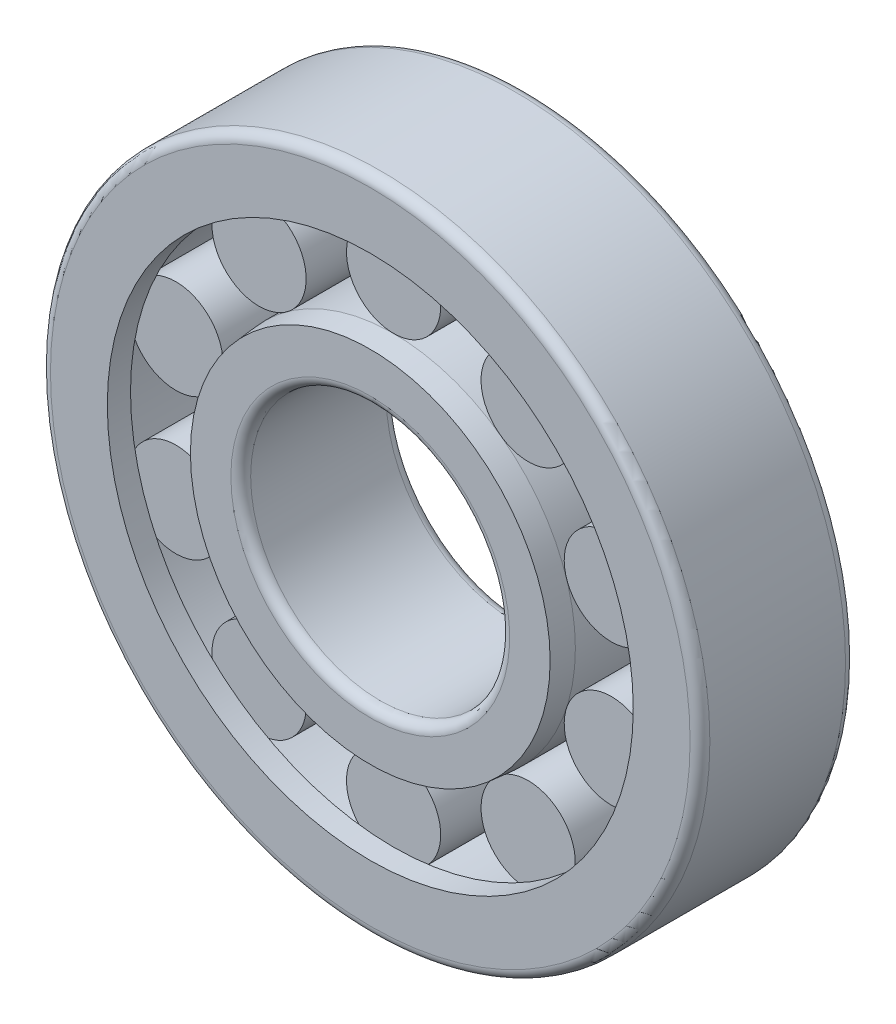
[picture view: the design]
ISO-10303-21;
HEADER;
FILE_DESCRIPTION(('STEP AP214'),'2;1');
FILE_NAME('part.step','',(''),(''),'','','');
FILE_SCHEMA(('AUTOMOTIVE_DESIGN { 1 0 10303 214 1 1 1 1 }'));
ENDSEC;
DATA;
#1=APPLICATION_CONTEXT('core data for automotive mechanical design processes');
#2=APPLICATION_PROTOCOL_DEFINITION('international standard','automotive_design',2000,#1);
#3=PRODUCT_CONTEXT('',#1,'mechanical');
#4=PRODUCT('Part','Part','',(#3));
#5=PRODUCT_RELATED_PRODUCT_CATEGORY('part','',(#4));
#6=PRODUCT_DEFINITION_FORMATION('','',#4);
#7=PRODUCT_DEFINITION_CONTEXT('part definition',#1,'design');
#8=PRODUCT_DEFINITION('design','',#6,#7);
#9=PRODUCT_DEFINITION_SHAPE('','',#8);
#10=(LENGTH_UNIT() NAMED_UNIT(*) SI_UNIT(.MILLI.,.METRE.));
#11=(NAMED_UNIT(*) PLANE_ANGLE_UNIT() SI_UNIT($,.RADIAN.));
#12=(NAMED_UNIT(*) SI_UNIT($,.STERADIAN.) SOLID_ANGLE_UNIT());
#13=UNCERTAINTY_MEASURE_WITH_UNIT(LENGTH_MEASURE(1.E-05),#10,'distance_accuracy_value','');
#14=(GEOMETRIC_REPRESENTATION_CONTEXT(3) GLOBAL_UNCERTAINTY_ASSIGNED_CONTEXT((#13)) GLOBAL_UNIT_ASSIGNED_CONTEXT((#10,
#11,#12)) REPRESENTATION_CONTEXT('',''));
#15=CARTESIAN_POINT('',(0.,0.,0.));
#16=DIRECTION('',(0.,0.,1.));
#17=DIRECTION('',(1.,0.,0.));
#18=AXIS2_PLACEMENT_3D('',#15,#16,#17);
#19=CARTESIAN_POINT('',(0.,27.5,16.5));
#20=DIRECTION('',(0.,0.,-1.));
#21=DIRECTION('',(-1.,0.,0.));
#22=AXIS2_PLACEMENT_3D('',#19,#20,#21);
#23=PLANE('',#22);
#24=CARTESIAN_POINT('',(0.,0.,16.5));
#25=DIRECTION('',(0.,0.,-1.));
#26=DIRECTION('',(-1.,0.,0.));
#27=AXIS2_PLACEMENT_3D('',#24,#25,#26);
#28=CIRCLE('',#27,29.6);
#29=CARTESIAN_POINT('',(-29.6,0.,16.5));
#30=VERTEX_POINT('',#29);
#31=EDGE_CURVE('E546',#30,#30,#28,.T.);
#32=ORIENTED_EDGE('',*,*,#31,.T.);
#33=EDGE_LOOP('',(#32));
#34=FACE_BOUND('',#33,.T.);
#35=CARTESIAN_POINT('',(0.,0.,16.5));
#36=DIRECTION('',(0.,0.,1.));
#37=DIRECTION('',(1.,0.,0.));
#38=AXIS2_PLACEMENT_3D('',#35,#36,#37);
#39=CIRCLE('',#38,38.1891183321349);
#40=CARTESIAN_POINT('',(38.1891183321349,0.,16.5));
#41=VERTEX_POINT('',#40);
#42=EDGE_CURVE('E475',#41,#41,#39,.T.);
#43=ORIENTED_EDGE('',*,*,#42,.T.);
#44=EDGE_LOOP('',(#43));
#45=FACE_BOUND('',#44,.T.);
#46=ADVANCED_FACE('F41',(#34,#45),#23,.F.);
#47=CARTESIAN_POINT('',(0.,27.5,-16.5));
#48=DIRECTION('',(0.,0.,1.));
#49=DIRECTION('',(1.,0.,0.));
#50=AXIS2_PLACEMENT_3D('',#47,#48,#49);
#51=PLANE('',#50);
#52=CARTESIAN_POINT('',(0.,0.,-16.5));
#53=DIRECTION('',(0.,0.,1.));
#54=DIRECTION('',(1.,0.,0.));
#55=AXIS2_PLACEMENT_3D('',#52,#53,#54);
#56=CIRCLE('',#55,29.6);
#57=CARTESIAN_POINT('',(29.6,0.,-16.5));
#58=VERTEX_POINT('',#57);
#59=EDGE_CURVE('E537',#58,#58,#56,.T.);
#60=ORIENTED_EDGE('',*,*,#59,.T.);
#61=EDGE_LOOP('',(#60));
#62=FACE_BOUND('',#61,.T.);
#63=CARTESIAN_POINT('',(0.,0.,-16.5));
#64=DIRECTION('',(0.,0.,1.));
#65=DIRECTION('',(1.,0.,0.));
#66=AXIS2_PLACEMENT_3D('',#63,#64,#65);
#67=CIRCLE('',#66,38.1891183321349);
#68=CARTESIAN_POINT('',(38.1891183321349,0.,-16.5));
#69=VERTEX_POINT('',#68);
#70=EDGE_CURVE('E481',#69,#69,#67,.T.);
#71=ORIENTED_EDGE('',*,*,#70,.F.);
#72=EDGE_LOOP('',(#71));
#73=FACE_BOUND('',#72,.T.);
#74=ADVANCED_FACE('F681',(#62,#73),#51,.F.);
#75=CARTESIAN_POINT('',(0.,38.6,11.55));
#76=DIRECTION('',(0.,0.,1.));
#77=DIRECTION('',(1.,0.,0.));
#78=AXIS2_PLACEMENT_3D('',#75,#76,#77);
#79=PLANE('',#78);
#80=CARTESIAN_POINT('',(0.,48.6,11.55));
#81=DIRECTION('',(0.,0.,1.));
#82=DIRECTION('',(1.,0.,0.));
#83=AXIS2_PLACEMENT_3D('',#80,#81,#82);
#84=CIRCLE('',#83,10.);
#85=CARTESIAN_POINT('',(-0.694003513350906,58.5758888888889,11.55));
#86=VERTEX_POINT('',#85);
#87=CARTESIAN_POINT('',(-0.563493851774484,38.6158888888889,11.55));
#88=VERTEX_POINT('',#87);
#89=EDGE_CURVE('E518',#86,#88,#84,.T.);
#90=ORIENTED_EDGE('',*,*,#89,.T.);
#91=CARTESIAN_POINT('',(0.,0.,11.55));
#92=DIRECTION('',(0.,0.,1.));
#93=DIRECTION('',(1.,0.,0.));
#94=AXIS2_PLACEMENT_3D('',#91,#92,#93);
#95=CIRCLE('',#94,38.62);
#96=CARTESIAN_POINT('',(0.563493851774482,38.6158888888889,11.55));
#97=VERTEX_POINT('',#96);
#98=EDGE_CURVE('E490',#88,#97,#95,.F.);
#99=ORIENTED_EDGE('',*,*,#98,.T.);
#100=CARTESIAN_POINT('',(0.694003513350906,58.5758888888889,11.55));
#101=VERTEX_POINT('',#100);
#102=EDGE_CURVE('E517',#97,#101,#84,.T.);
#103=ORIENTED_EDGE('',*,*,#102,.T.);
#104=CARTESIAN_POINT('',(0.,0.,11.55));
#105=DIRECTION('',(0.,0.,1.));
#106=DIRECTION('',(1.,0.,0.));
#107=AXIS2_PLACEMENT_3D('',#104,#105,#106);
#108=CIRCLE('',#107,58.58);
#109=EDGE_CURVE('E514',#101,#86,#108,.T.);
#110=ORIENTED_EDGE('',*,*,#109,.T.);
#111=EDGE_LOOP('',(#90,#99,#103,#110));
#112=FACE_BOUND('',#111,.T.);
#113=ADVANCED_FACE('F689',(#112),#79,.T.);
#114=CARTESIAN_POINT('',(0.,38.6,-11.55));
#115=DIRECTION('',(0.,0.,-1.));
#116=DIRECTION('',(-1.,0.,0.));
#117=AXIS2_PLACEMENT_3D('',#114,#115,#116);
#118=PLANE('',#117);
#119=CARTESIAN_POINT('',(0.,48.6,-11.55));
#120=DIRECTION('',(0.,0.,1.));
#121=DIRECTION('',(1.,0.,0.));
#122=AXIS2_PLACEMENT_3D('',#119,#120,#121);
#123=CIRCLE('',#122,10.);
#124=CARTESIAN_POINT('',(0.563493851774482,38.6158888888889,-11.55));
#125=VERTEX_POINT('',#124);
#126=CARTESIAN_POINT('',(0.694003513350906,58.5758888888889,-11.55));
#127=VERTEX_POINT('',#126);
#128=EDGE_CURVE('E521',#125,#127,#123,.T.);
#129=ORIENTED_EDGE('',*,*,#128,.F.);
#130=CARTESIAN_POINT('',(0.,0.,-11.55));
#131=DIRECTION('',(0.,0.,-1.));
#132=DIRECTION('',(-1.,0.,0.));
#133=AXIS2_PLACEMENT_3D('',#130,#131,#132);
#134=CIRCLE('',#133,38.62);
#135=CARTESIAN_POINT('',(-0.563493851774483,38.6158888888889,-11.55));
#136=VERTEX_POINT('',#135);
#137=EDGE_CURVE('E487',#125,#136,#134,.F.);
#138=ORIENTED_EDGE('',*,*,#137,.T.);
#139=CARTESIAN_POINT('',(-0.694003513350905,58.5758888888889,-11.55));
#140=VERTEX_POINT('',#139);
#141=EDGE_CURVE('E522',#140,#136,#123,.T.);
#142=ORIENTED_EDGE('',*,*,#141,.F.);
#143=CARTESIAN_POINT('',(0.,0.,-11.55));
#144=DIRECTION('',(0.,0.,-1.));
#145=DIRECTION('',(-1.,0.,0.));
#146=AXIS2_PLACEMENT_3D('',#143,#144,#145);
#147=CIRCLE('',#146,58.58);
#148=EDGE_CURVE('E511',#140,#127,#147,.T.);
#149=ORIENTED_EDGE('',*,*,#148,.T.);
#150=EDGE_LOOP('',(#129,#138,#142,#149));
#151=FACE_BOUND('',#150,.T.);
#152=ADVANCED_FACE('F729',(#151),#118,.T.);
#153=CARTESIAN_POINT('',(0.,48.6,11.55));
#154=DIRECTION('',(0.,0.,1.));
#155=DIRECTION('',(1.,0.,0.));
#156=AXIS2_PLACEMENT_3D('',#153,#154,#155);
#157=CYLINDRICAL_SURFACE('',#156,10.);
#158=ORIENTED_EDGE('',*,*,#102,.F.);
#159=DIRECTION('',(0.,0.,1.));
#160=VECTOR('',#159,1.);
#161=CARTESIAN_POINT('',(0.563493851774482,38.6158888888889,0.));
#162=LINE('',#161,#160);
#163=EDGE_CURVE('E534',#97,#125,#162,.F.);
#164=ORIENTED_EDGE('',*,*,#163,.T.);
#165=ORIENTED_EDGE('',*,*,#128,.T.);
#166=DIRECTION('',(0.,0.,1.));
#167=VECTOR('',#166,1.);
#168=CARTESIAN_POINT('',(0.694003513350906,58.5758888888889,0.));
#169=LINE('',#168,#167);
#170=EDGE_CURVE('E528',#127,#101,#169,.T.);
#171=ORIENTED_EDGE('',*,*,#170,.T.);
#172=EDGE_LOOP('',(#158,#164,#165,#171));
#173=FACE_BOUND('',#172,.T.);
#174=ADVANCED_FACE('F726',(#173),#157,.T.);
#175=ORIENTED_EDGE('',*,*,#141,.T.);
#176=DIRECTION('',(0.,0.,1.));
#177=VECTOR('',#176,1.);
#178=CARTESIAN_POINT('',(-0.563493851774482,38.6158888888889,0.));
#179=LINE('',#178,#177);
#180=EDGE_CURVE('E531',#136,#88,#179,.T.);
#181=ORIENTED_EDGE('',*,*,#180,.T.);
#182=ORIENTED_EDGE('',*,*,#89,.F.);
#183=DIRECTION('',(0.,0.,1.));
#184=VECTOR('',#183,1.);
#185=CARTESIAN_POINT('',(-0.694003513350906,58.5758888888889,0.));
#186=LINE('',#185,#184);
#187=EDGE_CURVE('E525',#86,#140,#186,.F.);
#188=ORIENTED_EDGE('',*,*,#187,.T.);
#189=EDGE_LOOP('',(#175,#181,#182,#188));
#190=FACE_BOUND('',#189,.T.);
#191=ADVANCED_FACE('F724',(#190),#157,.T.);
#192=CARTESIAN_POINT('',(0.,70.,16.5));
#193=DIRECTION('',(0.,0.,-1.));
#194=DIRECTION('',(-1.,0.,0.));
#195=AXIS2_PLACEMENT_3D('',#192,#193,#194);
#196=PLANE('',#195);
#197=CARTESIAN_POINT('',(0.,0.,16.5));
#198=DIRECTION('',(0.,0.,-1.));
#199=DIRECTION('',(-1.,0.,0.));
#200=AXIS2_PLACEMENT_3D('',#197,#198,#199);
#201=CIRCLE('',#200,67.9);
#202=CARTESIAN_POINT('',(-67.9,0.,16.5));
#203=VERTEX_POINT('',#202);
#204=EDGE_CURVE('E558',#203,#203,#201,.F.);
#205=ORIENTED_EDGE('',*,*,#204,.T.);
#206=EDGE_LOOP('',(#205));
#207=FACE_BOUND('',#206,.T.);
#208=CARTESIAN_POINT('',(0.,0.,16.5));
#209=DIRECTION('',(0.,0.,1.));
#210=DIRECTION('',(1.,0.,0.));
#211=AXIS2_PLACEMENT_3D('',#208,#209,#210);
#212=CIRCLE('',#211,55.8333333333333);
#213=CARTESIAN_POINT('',(55.8333333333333,0.,16.5));
#214=VERTEX_POINT('',#213);
#215=EDGE_CURVE('E508',#214,#214,#212,.T.);
#216=ORIENTED_EDGE('',*,*,#215,.F.);
#217=EDGE_LOOP('',(#216));
#218=FACE_BOUND('',#217,.T.);
#219=ADVANCED_FACE('F720',(#207,#218),#196,.F.);
#220=CARTESIAN_POINT('',(0.,0.,50.3916163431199));
#221=DIRECTION('',(0.,0.,1.));
#222=DIRECTION('',(1.,0.,0.));
#223=AXIS2_PLACEMENT_3D('',#220,#221,#222);
#224=CYLINDRICAL_SURFACE('',#223,55.8333333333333);
#225=CARTESIAN_POINT('',(0.,0.,11.575));
#226=DIRECTION('',(0.,0.,1.));
#227=DIRECTION('',(1.,0.,0.));
#228=AXIS2_PLACEMENT_3D('',#225,#226,#227);
#229=CIRCLE('',#228,55.8333333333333);
#230=CARTESIAN_POINT('',(55.8333333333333,0.,11.575));
#231=VERTEX_POINT('',#230);
#232=EDGE_CURVE('E505',#231,#231,#229,.T.);
#233=ORIENTED_EDGE('',*,*,#232,.F.);
#234=EDGE_LOOP('',(#233));
#235=FACE_BOUND('',#234,.T.);
#236=ORIENTED_EDGE('',*,*,#215,.T.);
#237=EDGE_LOOP('',(#236));
#238=FACE_BOUND('',#237,.T.);
#239=ADVANCED_FACE('F716',(#235,#238),#224,.F.);
#240=CARTESIAN_POINT('',(0.,55.8333333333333,11.575));
#241=DIRECTION('',(0.,0.,1.));
#242=DIRECTION('',(1.,0.,0.));
#243=AXIS2_PLACEMENT_3D('',#240,#241,#242);
#244=PLANE('',#243);
#245=CARTESIAN_POINT('',(0.,0.,11.575));
#246=DIRECTION('',(0.,0.,1.));
#247=DIRECTION('',(1.,0.,0.));
#248=AXIS2_PLACEMENT_3D('',#245,#246,#247);
#249=CIRCLE('',#248,58.58);
#250=CARTESIAN_POINT('',(58.58,0.,11.575));
#251=VERTEX_POINT('',#250);
#252=EDGE_CURVE('E502',#251,#251,#249,.T.);
#253=ORIENTED_EDGE('',*,*,#252,.F.);
#254=EDGE_LOOP('',(#253));
#255=FACE_BOUND('',#254,.T.);
#256=ORIENTED_EDGE('',*,*,#232,.T.);
#257=EDGE_LOOP('',(#256));
#258=FACE_BOUND('',#257,.T.);
#259=ADVANCED_FACE('F713',(#255,#258),#244,.F.);
#260=CARTESIAN_POINT('',(0.,0.,50.3916163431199));
#261=DIRECTION('',(0.,0.,1.));
#262=DIRECTION('',(1.,0.,0.));
#263=AXIS2_PLACEMENT_3D('',#260,#261,#262);
#264=CYLINDRICAL_SURFACE('',#263,58.58);
#265=CARTESIAN_POINT('',(0.,0.,-11.55));
#266=DIRECTION('',(0.,0.,-1.));
#267=DIRECTION('',(-1.,0.,0.));
#268=AXIS2_PLACEMENT_3D('',#265,#266,#267);
#269=CIRCLE('',#268,58.58);
#270=CARTESIAN_POINT('',(-33.868582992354,47.796814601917,-11.55));
#271=VERTEX_POINT('',#270);
#272=CARTESIAN_POINT('',(-34.9915042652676,46.9809645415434,-11.55));
#273=VERTEX_POINT('',#272);
#274=EDGE_CURVE('E307',#271,#273,#269,.F.);
#275=ORIENTED_EDGE('',*,*,#274,.T.);
#276=DIRECTION('',(0.,0.,1.));
#277=VECTOR('',#276,1.);
#278=CARTESIAN_POINT('',(-34.9915042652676,46.9809645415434,0.));
#279=LINE('',#278,#277);
#280=CARTESIAN_POINT('',(-34.9915042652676,46.9809645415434,11.55));
#281=VERTEX_POINT('',#280);
#282=EDGE_CURVE('E298',#273,#281,#279,.T.);
#283=ORIENTED_EDGE('',*,*,#282,.T.);
#284=CARTESIAN_POINT('',(0.,0.,11.55));
#285=DIRECTION('',(0.,0.,1.));
#286=DIRECTION('',(1.,0.,0.));
#287=AXIS2_PLACEMENT_3D('',#284,#285,#286);
#288=CIRCLE('',#287,58.58);
#289=CARTESIAN_POINT('',(-33.868582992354,47.796814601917,11.55));
#290=VERTEX_POINT('',#289);
#291=EDGE_CURVE('E318',#281,#290,#288,.F.);
#292=ORIENTED_EDGE('',*,*,#291,.T.);
#293=DIRECTION('',(0.,0.,1.));
#294=VECTOR('',#293,1.);
#295=CARTESIAN_POINT('',(-33.868582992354,47.796814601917,0.));
#296=LINE('',#295,#294);
#297=EDGE_CURVE('E308',#290,#271,#296,.F.);
#298=ORIENTED_EDGE('',*,*,#297,.T.);
#299=EDGE_LOOP('',(#275,#283,#292,#298));
#300=FACE_BOUND('',#299,.T.);
#301=CARTESIAN_POINT('',(0.,0.,-11.55));
#302=DIRECTION('',(0.,0.,-1.));
#303=DIRECTION('',(-1.,0.,0.));
#304=AXIS2_PLACEMENT_3D('',#301,#302,#303);
#305=CIRCLE('',#304,58.58);
#306=CARTESIAN_POINT('',(-55.4945219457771,18.76098169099,-11.55));
#307=VERTEX_POINT('',#306);
#308=CARTESIAN_POINT('',(-55.9234397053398,17.4409085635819,-11.55));
#309=VERTEX_POINT('',#308);
#310=EDGE_CURVE('E336',#307,#309,#305,.F.);
#311=ORIENTED_EDGE('',*,*,#310,.T.);
#312=DIRECTION('',(0.,0.,1.));
#313=VECTOR('',#312,1.);
#314=CARTESIAN_POINT('',(-55.9234397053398,17.4409085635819,0.));
#315=LINE('',#314,#313);
#316=CARTESIAN_POINT('',(-55.9234397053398,17.4409085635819,11.55));
#317=VERTEX_POINT('',#316);
#318=EDGE_CURVE('E333',#309,#317,#315,.T.);
#319=ORIENTED_EDGE('',*,*,#318,.T.);
#320=CARTESIAN_POINT('',(0.,0.,11.55));
#321=DIRECTION('',(0.,0.,1.));
#322=DIRECTION('',(1.,0.,0.));
#323=AXIS2_PLACEMENT_3D('',#320,#321,#322);
#324=CIRCLE('',#323,58.58);
#325=CARTESIAN_POINT('',(-55.4945219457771,18.76098169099,11.55));
#326=VERTEX_POINT('',#325);
#327=EDGE_CURVE('E339',#317,#326,#324,.F.);
#328=ORIENTED_EDGE('',*,*,#327,.T.);
#329=DIRECTION('',(0.,0.,1.));
#330=VECTOR('',#329,1.);
#331=CARTESIAN_POINT('',(-55.4945219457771,18.76098169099,0.));
#332=LINE('',#331,#330);
#333=EDGE_CURVE('E330',#326,#307,#332,.F.);
#334=ORIENTED_EDGE('',*,*,#333,.T.);
#335=EDGE_LOOP('',(#311,#319,#328,#334));
#336=FACE_BOUND('',#335,.T.);
#337=CARTESIAN_POINT('',(0.,0.,-11.55));
#338=DIRECTION('',(0.,0.,-1.));
#339=DIRECTION('',(-1.,0.,0.));
#340=AXIS2_PLACEMENT_3D('',#337,#338,#339);
#341=CIRCLE('',#340,58.58);
#342=CARTESIAN_POINT('',(-55.9234397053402,-17.4409085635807,-11.55));
#343=VERTEX_POINT('',#342);
#344=CARTESIAN_POINT('',(-55.4945219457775,-18.7609816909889,-11.55));
#345=VERTEX_POINT('',#344);
#346=EDGE_CURVE('E355',#343,#345,#341,.F.);
#347=ORIENTED_EDGE('',*,*,#346,.T.);
#348=DIRECTION('',(0.,0.,1.));
#349=VECTOR('',#348,1.);
#350=CARTESIAN_POINT('',(-55.4945219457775,-18.7609816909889,0.));
#351=LINE('',#350,#349);
#352=CARTESIAN_POINT('',(-55.4945219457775,-18.7609816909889,11.55));
#353=VERTEX_POINT('',#352);
#354=EDGE_CURVE('E352',#345,#353,#351,.T.);
#355=ORIENTED_EDGE('',*,*,#354,.T.);
#356=CARTESIAN_POINT('',(0.,0.,11.55));
#357=DIRECTION('',(0.,0.,1.));
#358=DIRECTION('',(1.,0.,0.));
#359=AXIS2_PLACEMENT_3D('',#356,#357,#358);
#360=CIRCLE('',#359,58.58);
#361=CARTESIAN_POINT('',(-55.9234397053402,-17.4409085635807,11.55));
#362=VERTEX_POINT('',#361);
#363=EDGE_CURVE('E358',#353,#362,#360,.F.);
#364=ORIENTED_EDGE('',*,*,#363,.T.);
#365=DIRECTION('',(0.,0.,1.));
#366=VECTOR('',#365,1.);
#367=CARTESIAN_POINT('',(-55.9234397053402,-17.4409085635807,0.));
#368=LINE('',#367,#366);
#369=EDGE_CURVE('E349',#362,#343,#368,.F.);
#370=ORIENTED_EDGE('',*,*,#369,.T.);
#371=EDGE_LOOP('',(#347,#355,#364,#370));
#372=FACE_BOUND('',#371,.T.);
#373=CARTESIAN_POINT('',(0.,0.,-11.55));
#374=DIRECTION('',(0.,0.,-1.));
#375=DIRECTION('',(-1.,0.,0.));
#376=AXIS2_PLACEMENT_3D('',#373,#374,#375);
#377=CIRCLE('',#376,58.58);
#378=CARTESIAN_POINT('',(-34.9915042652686,-46.9809645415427,-11.55));
#379=VERTEX_POINT('',#378);
#380=CARTESIAN_POINT('',(-33.8685829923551,-47.7968146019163,-11.55));
#381=VERTEX_POINT('',#380);
#382=EDGE_CURVE('E374',#379,#381,#377,.F.);
#383=ORIENTED_EDGE('',*,*,#382,.T.);
#384=DIRECTION('',(0.,0.,1.));
#385=VECTOR('',#384,1.);
#386=CARTESIAN_POINT('',(-33.8685829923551,-47.7968146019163,0.));
#387=LINE('',#386,#385);
#388=CARTESIAN_POINT('',(-33.8685829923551,-47.7968146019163,11.55));
#389=VERTEX_POINT('',#388);
#390=EDGE_CURVE('E371',#381,#389,#387,.T.);
#391=ORIENTED_EDGE('',*,*,#390,.T.);
#392=CARTESIAN_POINT('',(0.,0.,11.55));
#393=DIRECTION('',(0.,0.,1.));
#394=DIRECTION('',(1.,0.,0.));
#395=AXIS2_PLACEMENT_3D('',#392,#393,#394);
#396=CIRCLE('',#395,58.58);
#397=CARTESIAN_POINT('',(-34.9915042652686,-46.9809645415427,11.55));
#398=VERTEX_POINT('',#397);
#399=EDGE_CURVE('E377',#389,#398,#396,.F.);
#400=ORIENTED_EDGE('',*,*,#399,.T.);
#401=DIRECTION('',(0.,0.,1.));
#402=VECTOR('',#401,1.);
#403=CARTESIAN_POINT('',(-34.9915042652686,-46.9809645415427,0.));
#404=LINE('',#403,#402);
#405=EDGE_CURVE('E368',#398,#379,#404,.F.);
#406=ORIENTED_EDGE('',*,*,#405,.T.);
#407=EDGE_LOOP('',(#383,#391,#400,#406));
#408=FACE_BOUND('',#407,.T.);
#409=CARTESIAN_POINT('',(0.,0.,-11.55));
#410=DIRECTION('',(0.,0.,-1.));
#411=DIRECTION('',(-1.,0.,0.));
#412=AXIS2_PLACEMENT_3D('',#409,#410,#411);
#413=CIRCLE('',#412,58.58);
#414=CARTESIAN_POINT('',(-0.694003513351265,-58.5758888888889,-11.55));
#415=VERTEX_POINT('',#414);
#416=CARTESIAN_POINT('',(0.694003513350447,-58.5758888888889,-11.55));
#417=VERTEX_POINT('',#416);
#418=EDGE_CURVE('E393',#415,#417,#413,.F.);
#419=ORIENTED_EDGE('',*,*,#418,.T.);
#420=DIRECTION('',(0.,0.,1.));
#421=VECTOR('',#420,1.);
#422=CARTESIAN_POINT('',(0.694003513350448,-58.5758888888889,0.));
#423=LINE('',#422,#421);
#424=CARTESIAN_POINT('',(0.694003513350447,-58.5758888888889,11.55));
#425=VERTEX_POINT('',#424);
#426=EDGE_CURVE('E390',#417,#425,#423,.T.);
#427=ORIENTED_EDGE('',*,*,#426,.T.);
#428=CARTESIAN_POINT('',(0.,0.,11.55));
#429=DIRECTION('',(0.,0.,1.));
#430=DIRECTION('',(1.,0.,0.));
#431=AXIS2_PLACEMENT_3D('',#428,#429,#430);
#432=CIRCLE('',#431,58.58);
#433=CARTESIAN_POINT('',(-0.694003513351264,-58.5758888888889,11.55));
#434=VERTEX_POINT('',#433);
#435=EDGE_CURVE('E396',#425,#434,#432,.F.);
#436=ORIENTED_EDGE('',*,*,#435,.T.);
#437=DIRECTION('',(0.,0.,1.));
#438=VECTOR('',#437,1.);
#439=CARTESIAN_POINT('',(-0.694003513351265,-58.5758888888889,0.));
#440=LINE('',#439,#438);
#441=EDGE_CURVE('E387',#434,#415,#440,.F.);
#442=ORIENTED_EDGE('',*,*,#441,.T.);
#443=EDGE_LOOP('',(#419,#427,#436,#442));
#444=FACE_BOUND('',#443,.T.);
#445=CARTESIAN_POINT('',(0.,0.,-11.55));
#446=DIRECTION('',(0.,0.,-1.));
#447=DIRECTION('',(-1.,0.,0.));
#448=AXIS2_PLACEMENT_3D('',#445,#446,#447);
#449=CIRCLE('',#448,58.58);
#450=CARTESIAN_POINT('',(33.8685829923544,-47.7968146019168,-11.55));
#451=VERTEX_POINT('',#450);
#452=CARTESIAN_POINT('',(34.9915042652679,-46.9809645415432,-11.55));
#453=VERTEX_POINT('',#452);
#454=EDGE_CURVE('E412',#451,#453,#449,.F.);
#455=ORIENTED_EDGE('',*,*,#454,.T.);
#456=DIRECTION('',(0.,0.,1.));
#457=VECTOR('',#456,1.);
#458=CARTESIAN_POINT('',(34.9915042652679,-46.9809645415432,0.));
#459=LINE('',#458,#457);
#460=CARTESIAN_POINT('',(34.9915042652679,-46.9809645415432,11.55));
#461=VERTEX_POINT('',#460);
#462=EDGE_CURVE('E409',#453,#461,#459,.T.);
#463=ORIENTED_EDGE('',*,*,#462,.T.);
#464=CARTESIAN_POINT('',(0.,0.,11.55));
#465=DIRECTION('',(0.,0.,1.));
#466=DIRECTION('',(1.,0.,0.));
#467=AXIS2_PLACEMENT_3D('',#464,#465,#466);
#468=CIRCLE('',#467,58.58);
#469=CARTESIAN_POINT('',(33.8685829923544,-47.7968146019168,11.55));
#470=VERTEX_POINT('',#469);
#471=EDGE_CURVE('E415',#461,#470,#468,.F.);
#472=ORIENTED_EDGE('',*,*,#471,.T.);
#473=DIRECTION('',(0.,0.,1.));
#474=VECTOR('',#473,1.);
#475=CARTESIAN_POINT('',(33.8685829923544,-47.7968146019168,0.));
#476=LINE('',#475,#474);
#477=EDGE_CURVE('E406',#470,#451,#476,.F.);
#478=ORIENTED_EDGE('',*,*,#477,.T.);
#479=EDGE_LOOP('',(#455,#463,#472,#478));
#480=FACE_BOUND('',#479,.T.);
#481=CARTESIAN_POINT('',(0.,0.,-11.55));
#482=DIRECTION('',(0.,0.,-1.));
#483=DIRECTION('',(-1.,0.,0.));
#484=AXIS2_PLACEMENT_3D('',#481,#482,#483);
#485=CIRCLE('',#484,58.58);
#486=CARTESIAN_POINT('',(55.4945219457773,-18.7609816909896,-11.55));
#487=VERTEX_POINT('',#486);
#488=CARTESIAN_POINT('',(55.9234397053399,-17.4409085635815,-11.55));
#489=VERTEX_POINT('',#488);
#490=EDGE_CURVE('E431',#487,#489,#485,.F.);
#491=ORIENTED_EDGE('',*,*,#490,.T.);
#492=DIRECTION('',(0.,0.,1.));
#493=VECTOR('',#492,1.);
#494=CARTESIAN_POINT('',(55.9234397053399,-17.4409085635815,0.));
#495=LINE('',#494,#493);
#496=CARTESIAN_POINT('',(55.9234397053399,-17.4409085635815,11.55));
#497=VERTEX_POINT('',#496);
#498=EDGE_CURVE('E428',#489,#497,#495,.T.);
#499=ORIENTED_EDGE('',*,*,#498,.T.);
#500=CARTESIAN_POINT('',(0.,0.,11.55));
#501=DIRECTION('',(0.,0.,1.));
#502=DIRECTION('',(1.,0.,0.));
#503=AXIS2_PLACEMENT_3D('',#500,#501,#502);
#504=CIRCLE('',#503,58.58);
#505=CARTESIAN_POINT('',(55.4945219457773,-18.7609816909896,11.55));
#506=VERTEX_POINT('',#505);
#507=EDGE_CURVE('E434',#497,#506,#504,.F.);
#508=ORIENTED_EDGE('',*,*,#507,.T.);
#509=DIRECTION('',(0.,0.,1.));
#510=VECTOR('',#509,1.);
#511=CARTESIAN_POINT('',(55.4945219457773,-18.7609816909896,0.));
#512=LINE('',#511,#510);
#513=EDGE_CURVE('E425',#506,#487,#512,.F.);
#514=ORIENTED_EDGE('',*,*,#513,.T.);
#515=EDGE_LOOP('',(#491,#499,#508,#514));
#516=FACE_BOUND('',#515,.T.);
#517=CARTESIAN_POINT('',(0.,0.,-11.55));
#518=DIRECTION('',(0.,0.,-1.));
#519=DIRECTION('',(-1.,0.,0.));
#520=AXIS2_PLACEMENT_3D('',#517,#518,#519);
#521=CIRCLE('',#520,58.58);
#522=CARTESIAN_POINT('',(55.9234397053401,17.4409085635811,-11.55));
#523=VERTEX_POINT('',#522);
#524=CARTESIAN_POINT('',(55.4945219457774,18.7609816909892,-11.55));
#525=VERTEX_POINT('',#524);
#526=EDGE_CURVE('E450',#523,#525,#521,.F.);
#527=ORIENTED_EDGE('',*,*,#526,.T.);
#528=DIRECTION('',(0.,0.,1.));
#529=VECTOR('',#528,1.);
#530=CARTESIAN_POINT('',(55.4945219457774,18.7609816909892,0.));
#531=LINE('',#530,#529);
#532=CARTESIAN_POINT('',(55.4945219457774,18.7609816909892,11.55));
#533=VERTEX_POINT('',#532);
#534=EDGE_CURVE('E447',#525,#533,#531,.T.);
#535=ORIENTED_EDGE('',*,*,#534,.T.);
#536=CARTESIAN_POINT('',(0.,0.,11.55));
#537=DIRECTION('',(0.,0.,1.));
#538=DIRECTION('',(1.,0.,0.));
#539=AXIS2_PLACEMENT_3D('',#536,#537,#538);
#540=CIRCLE('',#539,58.58);
#541=CARTESIAN_POINT('',(55.9234397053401,17.4409085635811,11.55));
#542=VERTEX_POINT('',#541);
#543=EDGE_CURVE('E453',#533,#542,#540,.F.);
#544=ORIENTED_EDGE('',*,*,#543,.T.);
#545=DIRECTION('',(0.,0.,1.));
#546=VECTOR('',#545,1.);
#547=CARTESIAN_POINT('',(55.9234397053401,17.4409085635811,0.));
#548=LINE('',#547,#546);
#549=EDGE_CURVE('E444',#542,#523,#548,.F.);
#550=ORIENTED_EDGE('',*,*,#549,.T.);
#551=EDGE_LOOP('',(#527,#535,#544,#550));
#552=FACE_BOUND('',#551,.T.);
#553=CARTESIAN_POINT('',(0.,0.,-11.55));
#554=DIRECTION('',(0.,0.,-1.));
#555=DIRECTION('',(-1.,0.,0.));
#556=AXIS2_PLACEMENT_3D('',#553,#554,#555);
#557=CIRCLE('',#556,58.58);
#558=CARTESIAN_POINT('',(34.9915042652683,46.9809645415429,-11.55));
#559=VERTEX_POINT('',#558);
#560=CARTESIAN_POINT('',(33.8685829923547,47.7968146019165,-11.55));
#561=VERTEX_POINT('',#560);
#562=EDGE_CURVE('E469',#559,#561,#557,.F.);
#563=ORIENTED_EDGE('',*,*,#562,.T.);
#564=DIRECTION('',(0.,0.,1.));
#565=VECTOR('',#564,1.);
#566=CARTESIAN_POINT('',(33.8685829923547,47.7968146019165,0.));
#567=LINE('',#566,#565);
#568=CARTESIAN_POINT('',(33.8685829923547,47.7968146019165,11.55));
#569=VERTEX_POINT('',#568);
#570=EDGE_CURVE('E466',#561,#569,#567,.T.);
#571=ORIENTED_EDGE('',*,*,#570,.T.);
#572=CARTESIAN_POINT('',(0.,0.,11.55));
#573=DIRECTION('',(0.,0.,1.));
#574=DIRECTION('',(1.,0.,0.));
#575=AXIS2_PLACEMENT_3D('',#572,#573,#574);
#576=CIRCLE('',#575,58.58);
#577=CARTESIAN_POINT('',(34.9915042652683,46.9809645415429,11.55));
#578=VERTEX_POINT('',#577);
#579=EDGE_CURVE('E472',#569,#578,#576,.F.);
#580=ORIENTED_EDGE('',*,*,#579,.T.);
#581=DIRECTION('',(0.,0.,1.));
#582=VECTOR('',#581,1.);
#583=CARTESIAN_POINT('',(34.9915042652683,46.9809645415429,0.));
#584=LINE('',#583,#582);
#585=EDGE_CURVE('E463',#578,#559,#584,.F.);
#586=ORIENTED_EDGE('',*,*,#585,.T.);
#587=EDGE_LOOP('',(#563,#571,#580,#586));
#588=FACE_BOUND('',#587,.T.);
#589=ORIENTED_EDGE('',*,*,#170,.F.);
#590=ORIENTED_EDGE('',*,*,#148,.F.);
#591=ORIENTED_EDGE('',*,*,#187,.F.);
#592=ORIENTED_EDGE('',*,*,#109,.F.);
#593=EDGE_LOOP('',(#589,#590,#591,#592));
#594=FACE_BOUND('',#593,.T.);
#595=CARTESIAN_POINT('',(0.,0.,-11.575));
#596=DIRECTION('',(0.,0.,1.));
#597=DIRECTION('',(1.,0.,0.));
#598=AXIS2_PLACEMENT_3D('',#595,#596,#597);
#599=CIRCLE('',#598,58.58);
#600=CARTESIAN_POINT('',(58.58,0.,-11.575));
#601=VERTEX_POINT('',#600);
#602=EDGE_CURVE('E499',#601,#601,#599,.T.);
#603=ORIENTED_EDGE('',*,*,#602,.F.);
#604=EDGE_LOOP('',(#603));
#605=FACE_BOUND('',#604,.T.);
#606=ORIENTED_EDGE('',*,*,#252,.T.);
#607=EDGE_LOOP('',(#606));
#608=FACE_BOUND('',#607,.T.);
#609=ADVANCED_FACE('F316',(#300,#336,#372,#408,#444,#480,#516,#552,#588,#594,#605,#608),#264,.F.);
#610=CARTESIAN_POINT('',(0.,55.8333333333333,-11.575));
#611=DIRECTION('',(0.,0.,-1.));
#612=DIRECTION('',(-1.,0.,0.));
#613=AXIS2_PLACEMENT_3D('',#610,#611,#612);
#614=PLANE('',#613);
#615=CARTESIAN_POINT('',(0.,0.,-11.575));
#616=DIRECTION('',(0.,0.,1.));
#617=DIRECTION('',(1.,0.,0.));
#618=AXIS2_PLACEMENT_3D('',#615,#616,#617);
#619=CIRCLE('',#618,55.8333333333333);
#620=CARTESIAN_POINT('',(55.8333333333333,0.,-11.575));
#621=VERTEX_POINT('',#620);
#622=EDGE_CURVE('E496',#621,#621,#619,.T.);
#623=ORIENTED_EDGE('',*,*,#622,.F.);
#624=EDGE_LOOP('',(#623));
#625=FACE_BOUND('',#624,.T.);
#626=ORIENTED_EDGE('',*,*,#602,.T.);
#627=EDGE_LOOP('',(#626));
#628=FACE_BOUND('',#627,.T.);
#629=ADVANCED_FACE('F706',(#625,#628),#614,.F.);
#630=CARTESIAN_POINT('',(0.,0.,50.3916163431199));
#631=DIRECTION('',(0.,0.,1.));
#632=DIRECTION('',(1.,0.,0.));
#633=AXIS2_PLACEMENT_3D('',#630,#631,#632);
#634=CYLINDRICAL_SURFACE('',#633,55.8333333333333);
#635=CARTESIAN_POINT('',(0.,0.,-16.5));
#636=DIRECTION('',(0.,0.,1.));
#637=DIRECTION('',(1.,0.,0.));
#638=AXIS2_PLACEMENT_3D('',#635,#636,#637);
#639=CIRCLE('',#638,55.8333333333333);
#640=CARTESIAN_POINT('',(55.8333333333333,0.,-16.5));
#641=VERTEX_POINT('',#640);
#642=EDGE_CURVE('E493',#641,#641,#639,.T.);
#643=ORIENTED_EDGE('',*,*,#642,.F.);
#644=EDGE_LOOP('',(#643));
#645=FACE_BOUND('',#644,.T.);
#646=ORIENTED_EDGE('',*,*,#622,.T.);
#647=EDGE_LOOP('',(#646));
#648=FACE_BOUND('',#647,.T.);
#649=ADVANCED_FACE('F702',(#645,#648),#634,.F.);
#650=CARTESIAN_POINT('',(0.,70.,-16.5));
#651=DIRECTION('',(0.,0.,1.));
#652=DIRECTION('',(1.,0.,0.));
#653=AXIS2_PLACEMENT_3D('',#650,#651,#652);
#654=PLANE('',#653);
#655=CARTESIAN_POINT('',(0.,0.,-16.5));
#656=DIRECTION('',(0.,0.,1.));
#657=DIRECTION('',(1.,0.,0.));
#658=AXIS2_PLACEMENT_3D('',#655,#656,#657);
#659=CIRCLE('',#658,67.9);
#660=CARTESIAN_POINT('',(67.9,0.,-16.5));
#661=VERTEX_POINT('',#660);
#662=EDGE_CURVE('E555',#661,#661,#659,.F.);
#663=ORIENTED_EDGE('',*,*,#662,.T.);
#664=EDGE_LOOP('',(#663));
#665=FACE_BOUND('',#664,.T.);
#666=ORIENTED_EDGE('',*,*,#642,.T.);
#667=EDGE_LOOP('',(#666));
#668=FACE_BOUND('',#667,.T.);
#669=ADVANCED_FACE('F698',(#665,#668),#654,.F.);
#670=CARTESIAN_POINT('',(0.,0.,50.3916163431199));
#671=DIRECTION('',(0.,0.,1.));
#672=DIRECTION('',(1.,0.,0.));
#673=AXIS2_PLACEMENT_3D('',#670,#671,#672);
#674=CYLINDRICAL_SURFACE('',#673,70.);
#675=CARTESIAN_POINT('',(0.,0.,-14.4));
#676=DIRECTION('',(0.,0.,1.));
#677=DIRECTION('',(1.,0.,0.));
#678=AXIS2_PLACEMENT_3D('',#675,#676,#677);
#679=CIRCLE('',#678,70.);
#680=CARTESIAN_POINT('',(70.,0.,-14.4));
#681=VERTEX_POINT('',#680);
#682=EDGE_CURVE('E552',#681,#681,#679,.T.);
#683=ORIENTED_EDGE('',*,*,#682,.T.);
#684=EDGE_LOOP('',(#683));
#685=FACE_BOUND('',#684,.T.);
#686=CARTESIAN_POINT('',(0.,0.,14.4));
#687=DIRECTION('',(0.,0.,-1.));
#688=DIRECTION('',(-1.,0.,0.));
#689=AXIS2_PLACEMENT_3D('',#686,#687,#688);
#690=CIRCLE('',#689,70.);
#691=CARTESIAN_POINT('',(-70.,0.,14.4));
#692=VERTEX_POINT('',#691);
#693=EDGE_CURVE('E549',#692,#692,#690,.T.);
#694=ORIENTED_EDGE('',*,*,#693,.T.);
#695=EDGE_LOOP('',(#694));
#696=FACE_BOUND('',#695,.T.);
#697=ADVANCED_FACE('F695',(#685,#696),#674,.T.);
#698=CARTESIAN_POINT('',(0.,0.,70.8625909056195));
#699=DIRECTION('',(0.,0.,1.));
#700=DIRECTION('',(1.,0.,0.));
#701=AXIS2_PLACEMENT_3D('',#698,#699,#700);
#702=CYLINDRICAL_SURFACE('',#701,38.62);
#703=CARTESIAN_POINT('',(0.,0.,11.55));
#704=DIRECTION('',(0.,0.,1.));
#705=DIRECTION('',(1.,0.,0.));
#706=AXIS2_PLACEMENT_3D('',#703,#704,#705);
#707=CIRCLE('',#706,38.62);
#708=CARTESIAN_POINT('',(-22.2419738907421,31.5721237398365,11.55));
#709=VERTEX_POINT('',#708);
#710=CARTESIAN_POINT('',(-23.1537260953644,30.9096969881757,11.55));
#711=VERTEX_POINT('',#710);
#712=EDGE_CURVE('E49',#709,#711,#707,.T.);
#713=ORIENTED_EDGE('',*,*,#712,.T.);
#714=DIRECTION('',(0.,0.,1.));
#715=VECTOR('',#714,1.);
#716=CARTESIAN_POINT('',(-23.1537260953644,30.9096969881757,0.));
#717=LINE('',#716,#715);
#718=CARTESIAN_POINT('',(-23.1537260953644,30.9096969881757,-11.55));
#719=VERTEX_POINT('',#718);
#720=EDGE_CURVE('E11',#711,#719,#717,.F.);
#721=ORIENTED_EDGE('',*,*,#720,.T.);
#722=CARTESIAN_POINT('',(0.,0.,-11.55));
#723=DIRECTION('',(0.,0.,-1.));
#724=DIRECTION('',(-1.,0.,0.));
#725=AXIS2_PLACEMENT_3D('',#722,#723,#724);
#726=CIRCLE('',#725,38.62);
#727=CARTESIAN_POINT('',(-22.2419738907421,31.5721237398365,-11.55));
#728=VERTEX_POINT('',#727);
#729=EDGE_CURVE('E314',#719,#728,#726,.T.);
#730=ORIENTED_EDGE('',*,*,#729,.T.);
#731=DIRECTION('',(0.,0.,1.));
#732=VECTOR('',#731,1.);
#733=CARTESIAN_POINT('',(-22.2419738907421,31.5721237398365,0.));
#734=LINE('',#733,#732);
#735=EDGE_CURVE('E657',#728,#709,#734,.T.);
#736=ORIENTED_EDGE('',*,*,#735,.T.);
#737=EDGE_LOOP('',(#713,#721,#730,#736));
#738=FACE_BOUND('',#737,.T.);
#739=CARTESIAN_POINT('',(0.,0.,11.55));
#740=DIRECTION('',(0.,0.,1.));
#741=DIRECTION('',(1.,0.,0.));
#742=AXIS2_PLACEMENT_3D('',#739,#740,#741);
#743=CIRCLE('',#742,38.62);
#744=CARTESIAN_POINT('',(-36.5517635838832,12.4688804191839,11.55));
#745=VERTEX_POINT('',#744);
#746=CARTESIAN_POINT('',(-36.9000219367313,11.3970514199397,11.55));
#747=VERTEX_POINT('',#746);
#748=EDGE_CURVE('E651',#745,#747,#743,.T.);
#749=ORIENTED_EDGE('',*,*,#748,.T.);
#750=DIRECTION('',(0.,0.,1.));
#751=VECTOR('',#750,1.);
#752=CARTESIAN_POINT('',(-36.9000219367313,11.3970514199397,0.));
#753=LINE('',#752,#751);
#754=CARTESIAN_POINT('',(-36.9000219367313,11.3970514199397,-11.55));
#755=VERTEX_POINT('',#754);
#756=EDGE_CURVE('E654',#747,#755,#753,.F.);
#757=ORIENTED_EDGE('',*,*,#756,.T.);
#758=CARTESIAN_POINT('',(0.,0.,-11.55));
#759=DIRECTION('',(0.,0.,-1.));
#760=DIRECTION('',(-1.,0.,0.));
#761=AXIS2_PLACEMENT_3D('',#758,#759,#760);
#762=CIRCLE('',#761,38.62);
#763=CARTESIAN_POINT('',(-36.5517635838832,12.4688804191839,-11.55));
#764=VERTEX_POINT('',#763);
#765=EDGE_CURVE('E648',#755,#764,#762,.T.);
#766=ORIENTED_EDGE('',*,*,#765,.T.);
#767=DIRECTION('',(0.,0.,1.));
#768=VECTOR('',#767,1.);
#769=CARTESIAN_POINT('',(-36.5517635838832,12.4688804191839,0.));
#770=LINE('',#769,#768);
#771=EDGE_CURVE('E645',#764,#745,#770,.T.);
#772=ORIENTED_EDGE('',*,*,#771,.T.);
#773=EDGE_LOOP('',(#749,#757,#766,#772));
#774=FACE_BOUND('',#773,.T.);
#775=CARTESIAN_POINT('',(0.,0.,11.55));
#776=DIRECTION('',(0.,0.,1.));
#777=DIRECTION('',(1.,0.,0.));
#778=AXIS2_PLACEMENT_3D('',#775,#776,#777);
#779=CIRCLE('',#778,38.62);
#780=CARTESIAN_POINT('',(-36.9000219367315,-11.3970514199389,11.55));
#781=VERTEX_POINT('',#780);
#782=CARTESIAN_POINT('',(-36.5517635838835,-12.4688804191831,11.55));
#783=VERTEX_POINT('',#782);
#784=EDGE_CURVE('E639',#781,#783,#779,.T.);
#785=ORIENTED_EDGE('',*,*,#784,.T.);
#786=DIRECTION('',(0.,0.,1.));
#787=VECTOR('',#786,1.);
#788=CARTESIAN_POINT('',(-36.5517635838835,-12.4688804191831,0.));
#789=LINE('',#788,#787);
#790=CARTESIAN_POINT('',(-36.5517635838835,-12.4688804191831,-11.55));
#791=VERTEX_POINT('',#790);
#792=EDGE_CURVE('E642',#783,#791,#789,.F.);
#793=ORIENTED_EDGE('',*,*,#792,.T.);
#794=CARTESIAN_POINT('',(0.,0.,-11.55));
#795=DIRECTION('',(0.,0.,-1.));
#796=DIRECTION('',(-1.,0.,0.));
#797=AXIS2_PLACEMENT_3D('',#794,#795,#796);
#798=CIRCLE('',#797,38.62);
#799=CARTESIAN_POINT('',(-36.9000219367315,-11.3970514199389,-11.55));
#800=VERTEX_POINT('',#799);
#801=EDGE_CURVE('E636',#791,#800,#798,.T.);
#802=ORIENTED_EDGE('',*,*,#801,.T.);
#803=DIRECTION('',(0.,0.,1.));
#804=VECTOR('',#803,1.);
#805=CARTESIAN_POINT('',(-36.9000219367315,-11.3970514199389,0.));
#806=LINE('',#805,#804);
#807=EDGE_CURVE('E633',#800,#781,#806,.T.);
#808=ORIENTED_EDGE('',*,*,#807,.T.);
#809=EDGE_LOOP('',(#785,#793,#802,#808));
#810=FACE_BOUND('',#809,.T.);
#811=CARTESIAN_POINT('',(0.,0.,11.55));
#812=DIRECTION('',(0.,0.,1.));
#813=DIRECTION('',(1.,0.,0.));
#814=AXIS2_PLACEMENT_3D('',#811,#812,#813);
#815=CIRCLE('',#814,38.62);
#816=CARTESIAN_POINT('',(-23.1537260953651,-30.9096969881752,11.55));
#817=VERTEX_POINT('',#816);
#818=CARTESIAN_POINT('',(-22.2419738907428,-31.572123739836,11.55));
#819=VERTEX_POINT('',#818);
#820=EDGE_CURVE('E627',#817,#819,#815,.T.);
#821=ORIENTED_EDGE('',*,*,#820,.T.);
#822=DIRECTION('',(0.,0.,1.));
#823=VECTOR('',#822,1.);
#824=CARTESIAN_POINT('',(-22.2419738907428,-31.572123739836,0.));
#825=LINE('',#824,#823);
#826=CARTESIAN_POINT('',(-22.2419738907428,-31.572123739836,-11.55));
#827=VERTEX_POINT('',#826);
#828=EDGE_CURVE('E630',#819,#827,#825,.F.);
#829=ORIENTED_EDGE('',*,*,#828,.T.);
#830=CARTESIAN_POINT('',(0.,0.,-11.55));
#831=DIRECTION('',(0.,0.,-1.));
#832=DIRECTION('',(-1.,0.,0.));
#833=AXIS2_PLACEMENT_3D('',#830,#831,#832);
#834=CIRCLE('',#833,38.62);
#835=CARTESIAN_POINT('',(-23.1537260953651,-30.9096969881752,-11.55));
#836=VERTEX_POINT('',#835);
#837=EDGE_CURVE('E624',#827,#836,#834,.T.);
#838=ORIENTED_EDGE('',*,*,#837,.T.);
#839=DIRECTION('',(0.,0.,1.));
#840=VECTOR('',#839,1.);
#841=CARTESIAN_POINT('',(-23.1537260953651,-30.9096969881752,0.));
#842=LINE('',#841,#840);
#843=EDGE_CURVE('E621',#836,#817,#842,.T.);
#844=ORIENTED_EDGE('',*,*,#843,.T.);
#845=EDGE_LOOP('',(#821,#829,#838,#844));
#846=FACE_BOUND('',#845,.T.);
#847=CARTESIAN_POINT('',(0.,0.,11.55));
#848=DIRECTION('',(0.,0.,1.));
#849=DIRECTION('',(1.,0.,0.));
#850=AXIS2_PLACEMENT_3D('',#847,#848,#849);
#851=CIRCLE('',#850,38.62);
#852=CARTESIAN_POINT('',(-0.563493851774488,-38.6158888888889,11.55));
#853=VERTEX_POINT('',#852);
#854=CARTESIAN_POINT('',(0.563493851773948,-38.6158888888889,11.55));
#855=VERTEX_POINT('',#854);
#856=EDGE_CURVE('E615',#853,#855,#851,.T.);
#857=ORIENTED_EDGE('',*,*,#856,.T.);
#858=DIRECTION('',(0.,0.,1.));
#859=VECTOR('',#858,1.);
#860=CARTESIAN_POINT('',(0.563493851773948,-38.6158888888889,0.));
#861=LINE('',#860,#859);
#862=CARTESIAN_POINT('',(0.563493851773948,-38.6158888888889,-11.55));
#863=VERTEX_POINT('',#862);
#864=EDGE_CURVE('E618',#855,#863,#861,.F.);
#865=ORIENTED_EDGE('',*,*,#864,.T.);
#866=CARTESIAN_POINT('',(0.,0.,-11.55));
#867=DIRECTION('',(0.,0.,-1.));
#868=DIRECTION('',(-1.,0.,0.));
#869=AXIS2_PLACEMENT_3D('',#866,#867,#868);
#870=CIRCLE('',#869,38.62);
#871=CARTESIAN_POINT('',(-0.563493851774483,-38.6158888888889,-11.55));
#872=VERTEX_POINT('',#871);
#873=EDGE_CURVE('E612',#863,#872,#870,.T.);
#874=ORIENTED_EDGE('',*,*,#873,.T.);
#875=DIRECTION('',(0.,0.,1.));
#876=VECTOR('',#875,1.);
#877=CARTESIAN_POINT('',(-0.563493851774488,-38.6158888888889,0.));
#878=LINE('',#877,#876);
#879=EDGE_CURVE('E609',#872,#853,#878,.T.);
#880=ORIENTED_EDGE('',*,*,#879,.T.);
#881=EDGE_LOOP('',(#857,#865,#874,#880));
#882=FACE_BOUND('',#881,.T.);
#883=CARTESIAN_POINT('',(0.,0.,11.55));
#884=DIRECTION('',(0.,0.,1.));
#885=DIRECTION('',(1.,0.,0.));
#886=AXIS2_PLACEMENT_3D('',#883,#884,#885);
#887=CIRCLE('',#886,38.62);
#888=CARTESIAN_POINT('',(22.2419738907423,-31.5721237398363,11.55));
#889=VERTEX_POINT('',#888);
#890=CARTESIAN_POINT('',(23.1537260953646,-30.9096969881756,11.55));
#891=VERTEX_POINT('',#890);
#892=EDGE_CURVE('E603',#889,#891,#887,.T.);
#893=ORIENTED_EDGE('',*,*,#892,.T.);
#894=DIRECTION('',(0.,0.,1.));
#895=VECTOR('',#894,1.);
#896=CARTESIAN_POINT('',(23.1537260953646,-30.9096969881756,0.));
#897=LINE('',#896,#895);
#898=CARTESIAN_POINT('',(23.1537260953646,-30.9096969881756,-11.55));
#899=VERTEX_POINT('',#898);
#900=EDGE_CURVE('E606',#891,#899,#897,.F.);
#901=ORIENTED_EDGE('',*,*,#900,.T.);
#902=CARTESIAN_POINT('',(0.,0.,-11.55));
#903=DIRECTION('',(0.,0.,-1.));
#904=DIRECTION('',(-1.,0.,0.));
#905=AXIS2_PLACEMENT_3D('',#902,#903,#904);
#906=CIRCLE('',#905,38.62);
#907=CARTESIAN_POINT('',(22.2419738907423,-31.5721237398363,-11.55));
#908=VERTEX_POINT('',#907);
#909=EDGE_CURVE('E600',#899,#908,#906,.T.);
#910=ORIENTED_EDGE('',*,*,#909,.T.);
#911=DIRECTION('',(0.,0.,1.));
#912=VECTOR('',#911,1.);
#913=CARTESIAN_POINT('',(22.2419738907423,-31.5721237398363,0.));
#914=LINE('',#913,#912);
#915=EDGE_CURVE('E597',#908,#889,#914,.T.);
#916=ORIENTED_EDGE('',*,*,#915,.T.);
#917=EDGE_LOOP('',(#893,#901,#910,#916));
#918=FACE_BOUND('',#917,.T.);
#919=CARTESIAN_POINT('',(0.,0.,11.55));
#920=DIRECTION('',(0.,0.,1.));
#921=DIRECTION('',(1.,0.,0.));
#922=AXIS2_PLACEMENT_3D('',#919,#920,#921);
#923=CIRCLE('',#922,38.62);
#924=CARTESIAN_POINT('',(36.5517635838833,-12.4688804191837,11.55));
#925=VERTEX_POINT('',#924);
#926=CARTESIAN_POINT('',(36.9000219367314,-11.3970514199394,11.55));
#927=VERTEX_POINT('',#926);
#928=EDGE_CURVE('E591',#925,#927,#923,.T.);
#929=ORIENTED_EDGE('',*,*,#928,.T.);
#930=DIRECTION('',(0.,0.,1.));
#931=VECTOR('',#930,1.);
#932=CARTESIAN_POINT('',(36.9000219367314,-11.3970514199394,0.));
#933=LINE('',#932,#931);
#934=CARTESIAN_POINT('',(36.9000219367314,-11.3970514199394,-11.55));
#935=VERTEX_POINT('',#934);
#936=EDGE_CURVE('E594',#927,#935,#933,.F.);
#937=ORIENTED_EDGE('',*,*,#936,.T.);
#938=CARTESIAN_POINT('',(0.,0.,-11.55));
#939=DIRECTION('',(0.,0.,-1.));
#940=DIRECTION('',(-1.,0.,0.));
#941=AXIS2_PLACEMENT_3D('',#938,#939,#940);
#942=CIRCLE('',#941,38.62);
#943=CARTESIAN_POINT('',(36.5517635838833,-12.4688804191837,-11.55));
#944=VERTEX_POINT('',#943);
#945=EDGE_CURVE('E588',#935,#944,#942,.T.);
#946=ORIENTED_EDGE('',*,*,#945,.T.);
#947=DIRECTION('',(0.,0.,1.));
#948=VECTOR('',#947,1.);
#949=CARTESIAN_POINT('',(36.5517635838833,-12.4688804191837,0.));
#950=LINE('',#949,#948);
#951=EDGE_CURVE('E585',#944,#925,#950,.T.);
#952=ORIENTED_EDGE('',*,*,#951,.T.);
#953=EDGE_LOOP('',(#929,#937,#946,#952));
#954=FACE_BOUND('',#953,.T.);
#955=CARTESIAN_POINT('',(0.,0.,11.55));
#956=DIRECTION('',(0.,0.,1.));
#957=DIRECTION('',(1.,0.,0.));
#958=AXIS2_PLACEMENT_3D('',#955,#956,#957);
#959=CIRCLE('',#958,38.62);
#960=CARTESIAN_POINT('',(36.9000219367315,11.3970514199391,11.55));
#961=VERTEX_POINT('',#960);
#962=CARTESIAN_POINT('',(36.5517635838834,12.4688804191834,11.55));
#963=VERTEX_POINT('',#962);
#964=EDGE_CURVE('E579',#961,#963,#959,.T.);
#965=ORIENTED_EDGE('',*,*,#964,.T.);
#966=DIRECTION('',(0.,0.,1.));
#967=VECTOR('',#966,1.);
#968=CARTESIAN_POINT('',(36.5517635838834,12.4688804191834,0.));
#969=LINE('',#968,#967);
#970=CARTESIAN_POINT('',(36.5517635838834,12.4688804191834,-11.55));
#971=VERTEX_POINT('',#970);
#972=EDGE_CURVE('E582',#963,#971,#969,.F.);
#973=ORIENTED_EDGE('',*,*,#972,.T.);
#974=CARTESIAN_POINT('',(0.,0.,-11.55));
#975=DIRECTION('',(0.,0.,-1.));
#976=DIRECTION('',(-1.,0.,0.));
#977=AXIS2_PLACEMENT_3D('',#974,#975,#976);
#978=CIRCLE('',#977,38.62);
#979=CARTESIAN_POINT('',(36.9000219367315,11.3970514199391,-11.55));
#980=VERTEX_POINT('',#979);
#981=EDGE_CURVE('E576',#971,#980,#978,.T.);
#982=ORIENTED_EDGE('',*,*,#981,.T.);
#983=DIRECTION('',(0.,0.,1.));
#984=VECTOR('',#983,1.);
#985=CARTESIAN_POINT('',(36.9000219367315,11.3970514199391,0.));
#986=LINE('',#985,#984);
#987=EDGE_CURVE('E573',#980,#961,#986,.T.);
#988=ORIENTED_EDGE('',*,*,#987,.T.);
#989=EDGE_LOOP('',(#965,#973,#982,#988));
#990=FACE_BOUND('',#989,.T.);
#991=CARTESIAN_POINT('',(0.,0.,11.55));
#992=DIRECTION('',(0.,0.,1.));
#993=DIRECTION('',(1.,0.,0.));
#994=AXIS2_PLACEMENT_3D('',#991,#992,#993);
#995=CIRCLE('',#994,38.62);
#996=CARTESIAN_POINT('',(23.1537260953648,30.9096969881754,11.55));
#997=VERTEX_POINT('',#996);
#998=CARTESIAN_POINT('',(22.2419738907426,31.5721237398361,11.55));
#999=VERTEX_POINT('',#998);
#1000=EDGE_CURVE('E567',#997,#999,#995,.T.);
#1001=ORIENTED_EDGE('',*,*,#1000,.T.);
#1002=DIRECTION('',(0.,0.,1.));
#1003=VECTOR('',#1002,1.);
#1004=CARTESIAN_POINT('',(22.2419738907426,31.5721237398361,0.));
#1005=LINE('',#1004,#1003);
#1006=CARTESIAN_POINT('',(22.2419738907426,31.5721237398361,-11.55));
#1007=VERTEX_POINT('',#1006);
#1008=EDGE_CURVE('E570',#999,#1007,#1005,.F.);
#1009=ORIENTED_EDGE('',*,*,#1008,.T.);
#1010=CARTESIAN_POINT('',(0.,0.,-11.55));
#1011=DIRECTION('',(0.,0.,-1.));
#1012=DIRECTION('',(-1.,0.,0.));
#1013=AXIS2_PLACEMENT_3D('',#1010,#1011,#1012);
#1014=CIRCLE('',#1013,38.62);
#1015=CARTESIAN_POINT('',(23.1537260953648,30.9096969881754,-11.55));
#1016=VERTEX_POINT('',#1015);
#1017=EDGE_CURVE('E564',#1007,#1016,#1014,.T.);
#1018=ORIENTED_EDGE('',*,*,#1017,.T.);
#1019=DIRECTION('',(0.,0.,1.));
#1020=VECTOR('',#1019,1.);
#1021=CARTESIAN_POINT('',(23.1537260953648,30.9096969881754,0.));
#1022=LINE('',#1021,#1020);
#1023=EDGE_CURVE('E561',#1016,#997,#1022,.T.);
#1024=ORIENTED_EDGE('',*,*,#1023,.T.);
#1025=EDGE_LOOP('',(#1001,#1009,#1018,#1024));
#1026=FACE_BOUND('',#1025,.T.);
#1027=ORIENTED_EDGE('',*,*,#163,.F.);
#1028=ORIENTED_EDGE('',*,*,#98,.F.);
#1029=ORIENTED_EDGE('',*,*,#180,.F.);
#1030=ORIENTED_EDGE('',*,*,#137,.F.);
#1031=EDGE_LOOP('',(#1027,#1028,#1029,#1030));
#1032=FACE_BOUND('',#1031,.T.);
#1033=CARTESIAN_POINT('',(0.,0.,11.575));
#1034=DIRECTION('',(0.,0.,1.));
#1035=DIRECTION('',(1.,0.,0.));
#1036=AXIS2_PLACEMENT_3D('',#1033,#1034,#1035);
#1037=CIRCLE('',#1036,38.62);
#1038=CARTESIAN_POINT('',(38.62,0.,11.575));
#1039=VERTEX_POINT('',#1038);
#1040=EDGE_CURVE('E478',#1039,#1039,#1037,.T.);
#1041=ORIENTED_EDGE('',*,*,#1040,.F.);
#1042=EDGE_LOOP('',(#1041));
#1043=FACE_BOUND('',#1042,.T.);
#1044=CARTESIAN_POINT('',(0.,0.,-11.575));
#1045=DIRECTION('',(0.,0.,1.));
#1046=DIRECTION('',(1.,0.,0.));
#1047=AXIS2_PLACEMENT_3D('',#1044,#1045,#1046);
#1048=CIRCLE('',#1047,38.62);
#1049=CARTESIAN_POINT('',(38.62,0.,-11.575));
#1050=VERTEX_POINT('',#1049);
#1051=EDGE_CURVE('E484',#1050,#1050,#1048,.T.);
#1052=ORIENTED_EDGE('',*,*,#1051,.T.);
#1053=EDGE_LOOP('',(#1052));
#1054=FACE_BOUND('',#1053,.T.);
#1055=ADVANCED_FACE('F662',(#738,#774,#810,#846,#882,#918,#954,#990,#1026,#1032,#1043,#1054),
#702,.T.);
#1056=CARTESIAN_POINT('',(0.,0.,70.8625909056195));
#1057=DIRECTION('',(0.,0.,1.));
#1058=DIRECTION('',(1.,0.,0.));
#1059=AXIS2_PLACEMENT_3D('',#1056,#1057,#1058);
#1060=CYLINDRICAL_SURFACE('',#1059,27.5);
#1061=CARTESIAN_POINT('',(0.,0.,-14.4));
#1062=DIRECTION('',(0.,0.,1.));
#1063=DIRECTION('',(1.,0.,0.));
#1064=AXIS2_PLACEMENT_3D('',#1061,#1062,#1063);
#1065=CIRCLE('',#1064,27.5);
#1066=CARTESIAN_POINT('',(27.5,0.,-14.4));
#1067=VERTEX_POINT('',#1066);
#1068=EDGE_CURVE('E543',#1067,#1067,#1065,.F.);
#1069=ORIENTED_EDGE('',*,*,#1068,.T.);
#1070=EDGE_LOOP('',(#1069));
#1071=FACE_BOUND('',#1070,.T.);
#1072=CARTESIAN_POINT('',(0.,0.,14.4));
#1073=DIRECTION('',(0.,0.,-1.));
#1074=DIRECTION('',(-1.,0.,0.));
#1075=AXIS2_PLACEMENT_3D('',#1072,#1073,#1074);
#1076=CIRCLE('',#1075,27.5);
#1077=CARTESIAN_POINT('',(-27.5,0.,14.4));
#1078=VERTEX_POINT('',#1077);
#1079=EDGE_CURVE('E540',#1078,#1078,#1076,.F.);
#1080=ORIENTED_EDGE('',*,*,#1079,.T.);
#1081=EDGE_LOOP('',(#1080));
#1082=FACE_BOUND('',#1081,.T.);
#1083=ADVANCED_FACE('F741',(#1071,#1082),#1060,.F.);
#1084=CARTESIAN_POINT('',(0.,0.,-14.4));
#1085=DIRECTION('',(0.,0.,1.));
#1086=DIRECTION('',(1.,0.,0.));
#1087=AXIS2_PLACEMENT_3D('',#1084,#1085,#1086);
#1088=TOROIDAL_SURFACE('',#1087,29.6,2.1);
#1089=ORIENTED_EDGE('',*,*,#1068,.F.);
#1090=EDGE_LOOP('',(#1089));
#1091=FACE_BOUND('',#1090,.T.);
#1092=ORIENTED_EDGE('',*,*,#59,.F.);
#1093=EDGE_LOOP('',(#1092));
#1094=FACE_BOUND('',#1093,.T.);
#1095=ADVANCED_FACE('F737',(#1091,#1094),#1088,.T.);
#1096=CARTESIAN_POINT('',(0.,0.,14.4));
#1097=DIRECTION('',(0.,0.,-1.));
#1098=DIRECTION('',(-1.,0.,0.));
#1099=AXIS2_PLACEMENT_3D('',#1096,#1097,#1098);
#1100=TOROIDAL_SURFACE('',#1099,29.6,2.1);
#1101=ORIENTED_EDGE('',*,*,#31,.F.);
#1102=EDGE_LOOP('',(#1101));
#1103=FACE_BOUND('',#1102,.T.);
#1104=ORIENTED_EDGE('',*,*,#1079,.F.);
#1105=EDGE_LOOP('',(#1104));
#1106=FACE_BOUND('',#1105,.T.);
#1107=ADVANCED_FACE('F740',(#1103,#1106),#1100,.T.);
#1108=CARTESIAN_POINT('',(0.,0.,-14.4));
#1109=DIRECTION('',(0.,0.,1.));
#1110=DIRECTION('',(1.,0.,0.));
#1111=AXIS2_PLACEMENT_3D('',#1108,#1109,#1110);
#1112=TOROIDAL_SURFACE('',#1111,67.9,2.1);
#1113=ORIENTED_EDGE('',*,*,#662,.F.);
#1114=EDGE_LOOP('',(#1113));
#1115=FACE_BOUND('',#1114,.T.);
#1116=ORIENTED_EDGE('',*,*,#682,.F.);
#1117=EDGE_LOOP('',(#1116));
#1118=FACE_BOUND('',#1117,.T.);
#1119=ADVANCED_FACE('F744',(#1115,#1118),#1112,.T.);
#1120=CARTESIAN_POINT('',(0.,0.,14.4));
#1121=DIRECTION('',(0.,0.,-1.));
#1122=DIRECTION('',(-1.,0.,0.));
#1123=AXIS2_PLACEMENT_3D('',#1120,#1121,#1122);
#1124=TOROIDAL_SURFACE('',#1123,67.9,2.1);
#1125=ORIENTED_EDGE('',*,*,#693,.F.);
#1126=EDGE_LOOP('',(#1125));
#1127=FACE_BOUND('',#1126,.T.);
#1128=ORIENTED_EDGE('',*,*,#204,.F.);
#1129=EDGE_LOOP('',(#1128));
#1130=FACE_BOUND('',#1129,.T.);
#1131=ADVANCED_FACE('F43',(#1127,#1130),#1124,.T.);
#1132=CARTESIAN_POINT('',(0.,0.,-11.575));
#1133=DIRECTION('',(0.,0.,1.));
#1134=DIRECTION('',(1.,0.,0.));
#1135=AXIS2_PLACEMENT_3D('',#1132,#1133,#1134);
#1136=CONICAL_SURFACE('',#1135,38.62,0.0872664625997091);
#1137=ORIENTED_EDGE('',*,*,#70,.T.);
#1138=EDGE_LOOP('',(#1137));
#1139=FACE_BOUND('',#1138,.T.);
#1140=ORIENTED_EDGE('',*,*,#1051,.F.);
#1141=EDGE_LOOP('',(#1140));
#1142=FACE_BOUND('',#1141,.T.);
#1143=ADVANCED_FACE('F751',(#1139,#1142),#1136,.T.);
#1144=CARTESIAN_POINT('',(0.,0.,11.575));
#1145=DIRECTION('',(0.,0.,-1.));
#1146=DIRECTION('',(1.,0.,0.));
#1147=AXIS2_PLACEMENT_3D('',#1144,#1145,#1146);
#1148=CONICAL_SURFACE('',#1147,38.62,0.0872664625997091);
#1149=ORIENTED_EDGE('',*,*,#42,.F.);
#1150=EDGE_LOOP('',(#1149));
#1151=FACE_BOUND('',#1150,.T.);
#1152=ORIENTED_EDGE('',*,*,#1040,.T.);
#1153=EDGE_LOOP('',(#1152));
#1154=FACE_BOUND('',#1153,.T.);
#1155=ADVANCED_FACE('F776',(#1151,#1154),#1148,.T.);
#1156=CARTESIAN_POINT('',(22.6885107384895,31.2280559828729,11.55));
#1157=DIRECTION('',(0.,0.,1.));
#1158=DIRECTION('',(0.809016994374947,-0.587785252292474,0.));
#1159=AXIS2_PLACEMENT_3D('',#1156,#1157,#1158);
#1160=PLANE('',#1159);
#1161=ORIENTED_EDGE('',*,*,#579,.F.);
#1162=CARTESIAN_POINT('',(28.5663632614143,39.3182259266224,11.55));
#1163=DIRECTION('',(0.,0.,1.));
#1164=DIRECTION('',(0.809016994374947,-0.587785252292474,0.));
#1165=AXIS2_PLACEMENT_3D('',#1162,#1163,#1164);
#1166=CIRCLE('',#1165,10.);
#1167=EDGE_CURVE('E459',#569,#999,#1166,.T.);
#1168=ORIENTED_EDGE('',*,*,#1167,.T.);
#1169=ORIENTED_EDGE('',*,*,#1000,.F.);
#1170=EDGE_CURVE('E456',#997,#578,#1166,.T.);
#1171=ORIENTED_EDGE('',*,*,#1170,.T.);
#1172=EDGE_LOOP('',(#1161,#1168,#1169,#1171));
#1173=FACE_BOUND('',#1172,.T.);
#1174=ADVANCED_FACE('F781',(#1173),#1160,.T.);
#1175=CARTESIAN_POINT('',(22.6885107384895,31.2280559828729,-11.55));
#1176=DIRECTION('',(0.,0.,-1.));
#1177=DIRECTION('',(-0.809016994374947,0.587785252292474,0.));
#1178=AXIS2_PLACEMENT_3D('',#1175,#1176,#1177);
#1179=PLANE('',#1178);
#1180=ORIENTED_EDGE('',*,*,#562,.F.);
#1181=CARTESIAN_POINT('',(28.5663632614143,39.3182259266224,-11.55));
#1182=DIRECTION('',(0.,0.,1.));
#1183=DIRECTION('',(0.809016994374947,-0.587785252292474,0.));
#1184=AXIS2_PLACEMENT_3D('',#1181,#1182,#1183);
#1185=CIRCLE('',#1184,10.);
#1186=EDGE_CURVE('E460',#1016,#559,#1185,.T.);
#1187=ORIENTED_EDGE('',*,*,#1186,.F.);
#1188=ORIENTED_EDGE('',*,*,#1017,.F.);
#1189=EDGE_CURVE('E462',#561,#1007,#1185,.T.);
#1190=ORIENTED_EDGE('',*,*,#1189,.F.);
#1191=EDGE_LOOP('',(#1180,#1187,#1188,#1190));
#1192=FACE_BOUND('',#1191,.T.);
#1193=ADVANCED_FACE('F813',(#1192),#1179,.T.);
#1194=CARTESIAN_POINT('',(28.5663632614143,39.3182259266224,11.55));
#1195=DIRECTION('',(0.,0.,1.));
#1196=DIRECTION('',(0.809016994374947,-0.587785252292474,0.));
#1197=AXIS2_PLACEMENT_3D('',#1194,#1195,#1196);
#1198=CYLINDRICAL_SURFACE('',#1197,10.);
#1199=ORIENTED_EDGE('',*,*,#570,.F.);
#1200=ORIENTED_EDGE('',*,*,#1189,.T.);
#1201=ORIENTED_EDGE('',*,*,#1008,.F.);
#1202=ORIENTED_EDGE('',*,*,#1167,.F.);
#1203=EDGE_LOOP('',(#1199,#1200,#1201,#1202));
#1204=FACE_BOUND('',#1203,.T.);
#1205=ADVANCED_FACE('F825',(#1204),#1198,.T.);
#1206=ORIENTED_EDGE('',*,*,#585,.F.);
#1207=ORIENTED_EDGE('',*,*,#1170,.F.);
#1208=ORIENTED_EDGE('',*,*,#1023,.F.);
#1209=ORIENTED_EDGE('',*,*,#1186,.T.);
#1210=EDGE_LOOP('',(#1206,#1207,#1208,#1209));
#1211=FACE_BOUND('',#1210,.T.);
#1212=ADVANCED_FACE('F838',(#1211),#1198,.T.);
#1213=CARTESIAN_POINT('',(36.710781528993,11.9280559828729,11.55));
#1214=DIRECTION('',(0.,0.,1.));
#1215=DIRECTION('',(0.309016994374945,-0.951056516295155,0.));
#1216=AXIS2_PLACEMENT_3D('',#1213,#1214,#1215);
#1217=PLANE('',#1216);
#1218=ORIENTED_EDGE('',*,*,#543,.F.);
#1219=CARTESIAN_POINT('',(46.2213466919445,15.0182259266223,11.55));
#1220=DIRECTION('',(0.,0.,1.));
#1221=DIRECTION('',(0.309016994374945,-0.951056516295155,0.));
#1222=AXIS2_PLACEMENT_3D('',#1219,#1220,#1221);
#1223=CIRCLE('',#1222,10.);
#1224=EDGE_CURVE('E440',#533,#963,#1223,.T.);
#1225=ORIENTED_EDGE('',*,*,#1224,.T.);
#1226=ORIENTED_EDGE('',*,*,#964,.F.);
#1227=EDGE_CURVE('E437',#961,#542,#1223,.T.);
#1228=ORIENTED_EDGE('',*,*,#1227,.T.);
#1229=EDGE_LOOP('',(#1218,#1225,#1226,#1228));
#1230=FACE_BOUND('',#1229,.T.);
#1231=ADVANCED_FACE('F849',(#1230),#1217,.T.);
#1232=CARTESIAN_POINT('',(36.710781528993,11.9280559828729,-11.55));
#1233=DIRECTION('',(0.,0.,-1.));
#1234=DIRECTION('',(-0.309016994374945,0.951056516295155,0.));
#1235=AXIS2_PLACEMENT_3D('',#1232,#1233,#1234);
#1236=PLANE('',#1235);
#1237=ORIENTED_EDGE('',*,*,#526,.F.);
#1238=CARTESIAN_POINT('',(46.2213466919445,15.0182259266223,-11.55));
#1239=DIRECTION('',(0.,0.,1.));
#1240=DIRECTION('',(0.309016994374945,-0.951056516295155,0.));
#1241=AXIS2_PLACEMENT_3D('',#1238,#1239,#1240);
#1242=CIRCLE('',#1241,10.);
#1243=EDGE_CURVE('E441',#980,#523,#1242,.T.);
#1244=ORIENTED_EDGE('',*,*,#1243,.F.);
#1245=ORIENTED_EDGE('',*,*,#981,.F.);
#1246=EDGE_CURVE('E443',#525,#971,#1242,.T.);
#1247=ORIENTED_EDGE('',*,*,#1246,.F.);
#1248=EDGE_LOOP('',(#1237,#1244,#1245,#1247));
#1249=FACE_BOUND('',#1248,.T.);
#1250=ADVANCED_FACE('F859',(#1249),#1236,.T.);
#1251=CARTESIAN_POINT('',(46.2213466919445,15.0182259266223,11.55));
#1252=DIRECTION('',(0.,0.,1.));
#1253=DIRECTION('',(0.309016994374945,-0.951056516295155,0.));
#1254=AXIS2_PLACEMENT_3D('',#1251,#1252,#1253);
#1255=CYLINDRICAL_SURFACE('',#1254,10.);
#1256=ORIENTED_EDGE('',*,*,#534,.F.);
#1257=ORIENTED_EDGE('',*,*,#1246,.T.);
#1258=ORIENTED_EDGE('',*,*,#972,.F.);
#1259=ORIENTED_EDGE('',*,*,#1224,.F.);
#1260=EDGE_LOOP('',(#1256,#1257,#1258,#1259));
#1261=FACE_BOUND('',#1260,.T.);
#1262=ADVANCED_FACE('F870',(#1261),#1255,.T.);
#1263=ORIENTED_EDGE('',*,*,#549,.F.);
#1264=ORIENTED_EDGE('',*,*,#1227,.F.);
#1265=ORIENTED_EDGE('',*,*,#987,.F.);
#1266=ORIENTED_EDGE('',*,*,#1243,.T.);
#1267=EDGE_LOOP('',(#1263,#1264,#1265,#1266));
#1268=FACE_BOUND('',#1267,.T.);
#1269=ADVANCED_FACE('F881',(#1268),#1255,.T.);
#1270=CARTESIAN_POINT('',(36.7107815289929,-11.9280559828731,11.55));
#1271=DIRECTION('',(0.,0.,1.));
#1272=DIRECTION('',(-0.309016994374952,-0.951056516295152,0.));
#1273=AXIS2_PLACEMENT_3D('',#1270,#1271,#1272);
#1274=PLANE('',#1273);
#1275=ORIENTED_EDGE('',*,*,#507,.F.);
#1276=CARTESIAN_POINT('',(46.2213466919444,-15.0182259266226,11.55));
#1277=DIRECTION('',(0.,0.,1.));
#1278=DIRECTION('',(-0.309016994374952,-0.951056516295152,0.));
#1279=AXIS2_PLACEMENT_3D('',#1276,#1277,#1278);
#1280=CIRCLE('',#1279,10.);
#1281=EDGE_CURVE('E421',#497,#927,#1280,.T.);
#1282=ORIENTED_EDGE('',*,*,#1281,.T.);
#1283=ORIENTED_EDGE('',*,*,#928,.F.);
#1284=EDGE_CURVE('E418',#925,#506,#1280,.T.);
#1285=ORIENTED_EDGE('',*,*,#1284,.T.);
#1286=EDGE_LOOP('',(#1275,#1282,#1283,#1285));
#1287=FACE_BOUND('',#1286,.T.);
#1288=ADVANCED_FACE('F892',(#1287),#1274,.T.);
#1289=CARTESIAN_POINT('',(36.7107815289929,-11.9280559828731,-11.55));
#1290=DIRECTION('',(0.,0.,-1.));
#1291=DIRECTION('',(0.309016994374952,0.951056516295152,0.));
#1292=AXIS2_PLACEMENT_3D('',#1289,#1290,#1291);
#1293=PLANE('',#1292);
#1294=ORIENTED_EDGE('',*,*,#490,.F.);
#1295=CARTESIAN_POINT('',(46.2213466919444,-15.0182259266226,-11.55));
#1296=DIRECTION('',(0.,0.,1.));
#1297=DIRECTION('',(-0.309016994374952,-0.951056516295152,0.));
#1298=AXIS2_PLACEMENT_3D('',#1295,#1296,#1297);
#1299=CIRCLE('',#1298,10.);
#1300=EDGE_CURVE('E422',#944,#487,#1299,.T.);
#1301=ORIENTED_EDGE('',*,*,#1300,.F.);
#1302=ORIENTED_EDGE('',*,*,#945,.F.);
#1303=EDGE_CURVE('E424',#489,#935,#1299,.T.);
#1304=ORIENTED_EDGE('',*,*,#1303,.F.);
#1305=EDGE_LOOP('',(#1294,#1301,#1302,#1304));
#1306=FACE_BOUND('',#1305,.T.);
#1307=ADVANCED_FACE('F902',(#1306),#1293,.T.);
#1308=CARTESIAN_POINT('',(46.2213466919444,-15.0182259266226,11.55));
#1309=DIRECTION('',(0.,0.,1.));
#1310=DIRECTION('',(-0.309016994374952,-0.951056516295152,0.));
#1311=AXIS2_PLACEMENT_3D('',#1308,#1309,#1310);
#1312=CYLINDRICAL_SURFACE('',#1311,10.);
#1313=ORIENTED_EDGE('',*,*,#498,.F.);
#1314=ORIENTED_EDGE('',*,*,#1303,.T.);
#1315=ORIENTED_EDGE('',*,*,#936,.F.);
#1316=ORIENTED_EDGE('',*,*,#1281,.F.);
#1317=EDGE_LOOP('',(#1313,#1314,#1315,#1316));
#1318=FACE_BOUND('',#1317,.T.);
#1319=ADVANCED_FACE('F913',(#1318),#1312,.T.);
#1320=ORIENTED_EDGE('',*,*,#513,.F.);
#1321=ORIENTED_EDGE('',*,*,#1284,.F.);
#1322=ORIENTED_EDGE('',*,*,#951,.F.);
#1323=ORIENTED_EDGE('',*,*,#1300,.T.);
#1324=EDGE_LOOP('',(#1320,#1321,#1322,#1323));
#1325=FACE_BOUND('',#1324,.T.);
#1326=ADVANCED_FACE('F924',(#1325),#1312,.T.);
#1327=CARTESIAN_POINT('',(22.6885107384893,-31.2280559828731,11.55));
#1328=DIRECTION('',(0.,0.,1.));
#1329=DIRECTION('',(-0.809016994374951,-0.587785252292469,0.));
#1330=AXIS2_PLACEMENT_3D('',#1327,#1328,#1329);
#1331=PLANE('',#1330);
#1332=ORIENTED_EDGE('',*,*,#471,.F.);
#1333=CARTESIAN_POINT('',(28.566363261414,-39.3182259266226,11.55));
#1334=DIRECTION('',(0.,0.,1.));
#1335=DIRECTION('',(-0.809016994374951,-0.587785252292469,0.));
#1336=AXIS2_PLACEMENT_3D('',#1333,#1334,#1335);
#1337=CIRCLE('',#1336,10.);
#1338=EDGE_CURVE('E402',#461,#891,#1337,.T.);
#1339=ORIENTED_EDGE('',*,*,#1338,.T.);
#1340=ORIENTED_EDGE('',*,*,#892,.F.);
#1341=EDGE_CURVE('E399',#889,#470,#1337,.T.);
#1342=ORIENTED_EDGE('',*,*,#1341,.T.);
#1343=EDGE_LOOP('',(#1332,#1339,#1340,#1342));
#1344=FACE_BOUND('',#1343,.T.);
#1345=ADVANCED_FACE('F935',(#1344),#1331,.T.);
#1346=CARTESIAN_POINT('',(22.6885107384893,-31.2280559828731,-11.55));
#1347=DIRECTION('',(0.,0.,-1.));
#1348=DIRECTION('',(0.809016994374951,0.587785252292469,0.));
#1349=AXIS2_PLACEMENT_3D('',#1346,#1347,#1348);
#1350=PLANE('',#1349);
#1351=ORIENTED_EDGE('',*,*,#454,.F.);
#1352=CARTESIAN_POINT('',(28.566363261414,-39.3182259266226,-11.55));
#1353=DIRECTION('',(0.,0.,1.));
#1354=DIRECTION('',(-0.809016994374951,-0.587785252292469,0.));
#1355=AXIS2_PLACEMENT_3D('',#1352,#1353,#1354);
#1356=CIRCLE('',#1355,10.);
#1357=EDGE_CURVE('E403',#908,#451,#1356,.T.);
#1358=ORIENTED_EDGE('',*,*,#1357,.F.);
#1359=ORIENTED_EDGE('',*,*,#909,.F.);
#1360=EDGE_CURVE('E405',#453,#899,#1356,.T.);
#1361=ORIENTED_EDGE('',*,*,#1360,.F.);
#1362=EDGE_LOOP('',(#1351,#1358,#1359,#1361));
#1363=FACE_BOUND('',#1362,.T.);
#1364=ADVANCED_FACE('F945',(#1363),#1350,.T.);
#1365=CARTESIAN_POINT('',(28.566363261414,-39.3182259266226,11.55));
#1366=DIRECTION('',(0.,0.,1.));
#1367=DIRECTION('',(-0.809016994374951,-0.587785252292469,0.));
#1368=AXIS2_PLACEMENT_3D('',#1365,#1366,#1367);
#1369=CYLINDRICAL_SURFACE('',#1368,10.);
#1370=ORIENTED_EDGE('',*,*,#462,.F.);
#1371=ORIENTED_EDGE('',*,*,#1360,.T.);
#1372=ORIENTED_EDGE('',*,*,#900,.F.);
#1373=ORIENTED_EDGE('',*,*,#1338,.F.);
#1374=EDGE_LOOP('',(#1370,#1371,#1372,#1373));
#1375=FACE_BOUND('',#1374,.T.);
#1376=ADVANCED_FACE('F956',(#1375),#1369,.T.);
#1377=ORIENTED_EDGE('',*,*,#477,.F.);
#1378=ORIENTED_EDGE('',*,*,#1341,.F.);
#1379=ORIENTED_EDGE('',*,*,#915,.F.);
#1380=ORIENTED_EDGE('',*,*,#1357,.T.);
#1381=EDGE_LOOP('',(#1377,#1378,#1379,#1380));
#1382=FACE_BOUND('',#1381,.T.);
#1383=ADVANCED_FACE('F967',(#1382),#1369,.T.);
#1384=CARTESIAN_POINT('',(-2.6954235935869E-13,-38.6,11.55));
#1385=DIRECTION('',(0.,0.,1.));
#1386=DIRECTION('',(-1.,0.,0.));
#1387=AXIS2_PLACEMENT_3D('',#1384,#1385,#1386);
#1388=PLANE('',#1387);
#1389=ORIENTED_EDGE('',*,*,#435,.F.);
#1390=CARTESIAN_POINT('',(-3.39371986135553E-13,-48.6,11.55));
#1391=DIRECTION('',(0.,0.,1.));
#1392=DIRECTION('',(-1.,0.,0.));
#1393=AXIS2_PLACEMENT_3D('',#1390,#1391,#1392);
#1394=CIRCLE('',#1393,10.);
#1395=EDGE_CURVE('E383',#425,#855,#1394,.T.);
#1396=ORIENTED_EDGE('',*,*,#1395,.T.);
#1397=ORIENTED_EDGE('',*,*,#856,.F.);
#1398=EDGE_CURVE('E380',#853,#434,#1394,.T.);
#1399=ORIENTED_EDGE('',*,*,#1398,.T.);
#1400=EDGE_LOOP('',(#1389,#1396,#1397,#1399));
#1401=FACE_BOUND('',#1400,.T.);
#1402=ADVANCED_FACE('F978',(#1401),#1388,.T.);
#1403=CARTESIAN_POINT('',(-2.6954235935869E-13,-38.6,-11.55));
#1404=DIRECTION('',(0.,0.,-1.));
#1405=DIRECTION('',(1.,0.,0.));
#1406=AXIS2_PLACEMENT_3D('',#1403,#1404,#1405);
#1407=PLANE('',#1406);
#1408=ORIENTED_EDGE('',*,*,#418,.F.);
#1409=CARTESIAN_POINT('',(-3.39371986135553E-13,-48.6,-11.55));
#1410=DIRECTION('',(0.,0.,1.));
#1411=DIRECTION('',(-1.,0.,0.));
#1412=AXIS2_PLACEMENT_3D('',#1409,#1410,#1411);
#1413=CIRCLE('',#1412,10.);
#1414=EDGE_CURVE('E384',#872,#415,#1413,.T.);
#1415=ORIENTED_EDGE('',*,*,#1414,.F.);
#1416=ORIENTED_EDGE('',*,*,#873,.F.);
#1417=EDGE_CURVE('E386',#417,#863,#1413,.T.);
#1418=ORIENTED_EDGE('',*,*,#1417,.F.);
#1419=EDGE_LOOP('',(#1408,#1415,#1416,#1418));
#1420=FACE_BOUND('',#1419,.T.);
#1421=ADVANCED_FACE('F988',(#1420),#1407,.T.);
#1422=CARTESIAN_POINT('',(-3.39371986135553E-13,-48.6,11.55));
#1423=DIRECTION('',(0.,0.,1.));
#1424=DIRECTION('',(-1.,0.,0.));
#1425=AXIS2_PLACEMENT_3D('',#1422,#1423,#1424);
#1426=CYLINDRICAL_SURFACE('',#1425,10.);
#1427=ORIENTED_EDGE('',*,*,#426,.F.);
#1428=ORIENTED_EDGE('',*,*,#1417,.T.);
#1429=ORIENTED_EDGE('',*,*,#864,.F.);
#1430=ORIENTED_EDGE('',*,*,#1395,.F.);
#1431=EDGE_LOOP('',(#1427,#1428,#1429,#1430));
#1432=FACE_BOUND('',#1431,.T.);
#1433=ADVANCED_FACE('F999',(#1432),#1426,.T.);
#1434=ORIENTED_EDGE('',*,*,#441,.F.);
#1435=ORIENTED_EDGE('',*,*,#1398,.F.);
#1436=ORIENTED_EDGE('',*,*,#879,.F.);
#1437=ORIENTED_EDGE('',*,*,#1414,.T.);
#1438=EDGE_LOOP('',(#1434,#1435,#1436,#1437));
#1439=FACE_BOUND('',#1438,.T.);
#1440=ADVANCED_FACE('F1010',(#1439),#1426,.T.);
#1441=CARTESIAN_POINT('',(-22.6885107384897,-31.2280559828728,11.55));
#1442=DIRECTION('',(0.,0.,1.));
#1443=DIRECTION('',(-0.809016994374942,0.58778525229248,0.));
#1444=AXIS2_PLACEMENT_3D('',#1441,#1442,#1443);
#1445=PLANE('',#1444);
#1446=ORIENTED_EDGE('',*,*,#399,.F.);
#1447=CARTESIAN_POINT('',(-28.5663632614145,-39.3182259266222,11.55));
#1448=DIRECTION('',(0.,0.,1.));
#1449=DIRECTION('',(-0.809016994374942,0.58778525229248,0.));
#1450=AXIS2_PLACEMENT_3D('',#1447,#1448,#1449);
#1451=CIRCLE('',#1450,10.);
#1452=EDGE_CURVE('E364',#389,#819,#1451,.T.);
#1453=ORIENTED_EDGE('',*,*,#1452,.T.);
#1454=ORIENTED_EDGE('',*,*,#820,.F.);
#1455=EDGE_CURVE('E361',#817,#398,#1451,.T.);
#1456=ORIENTED_EDGE('',*,*,#1455,.T.);
#1457=EDGE_LOOP('',(#1446,#1453,#1454,#1456));
#1458=FACE_BOUND('',#1457,.T.);
#1459=ADVANCED_FACE('F1021',(#1458),#1445,.T.);
#1460=CARTESIAN_POINT('',(-22.6885107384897,-31.2280559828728,-11.55));
#1461=DIRECTION('',(0.,0.,-1.));
#1462=DIRECTION('',(0.809016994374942,-0.58778525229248,0.));
#1463=AXIS2_PLACEMENT_3D('',#1460,#1461,#1462);
#1464=PLANE('',#1463);
#1465=ORIENTED_EDGE('',*,*,#382,.F.);
#1466=CARTESIAN_POINT('',(-28.5663632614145,-39.3182259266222,-11.55));
#1467=DIRECTION('',(0.,0.,1.));
#1468=DIRECTION('',(-0.809016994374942,0.58778525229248,0.));
#1469=AXIS2_PLACEMENT_3D('',#1466,#1467,#1468);
#1470=CIRCLE('',#1469,10.);
#1471=EDGE_CURVE('E365',#836,#379,#1470,.T.);
#1472=ORIENTED_EDGE('',*,*,#1471,.F.);
#1473=ORIENTED_EDGE('',*,*,#837,.F.);
#1474=EDGE_CURVE('E367',#381,#827,#1470,.T.);
#1475=ORIENTED_EDGE('',*,*,#1474,.F.);
#1476=EDGE_LOOP('',(#1465,#1472,#1473,#1475));
#1477=FACE_BOUND('',#1476,.T.);
#1478=ADVANCED_FACE('F1031',(#1477),#1464,.T.);
#1479=CARTESIAN_POINT('',(-28.5663632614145,-39.3182259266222,11.55));
#1480=DIRECTION('',(0.,0.,1.));
#1481=DIRECTION('',(-0.809016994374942,0.58778525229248,0.));
#1482=AXIS2_PLACEMENT_3D('',#1479,#1480,#1481);
#1483=CYLINDRICAL_SURFACE('',#1482,10.);
#1484=ORIENTED_EDGE('',*,*,#390,.F.);
#1485=ORIENTED_EDGE('',*,*,#1474,.T.);
#1486=ORIENTED_EDGE('',*,*,#828,.F.);
#1487=ORIENTED_EDGE('',*,*,#1452,.F.);
#1488=EDGE_LOOP('',(#1484,#1485,#1486,#1487));
#1489=FACE_BOUND('',#1488,.T.);
#1490=ADVANCED_FACE('F1042',(#1489),#1483,.T.);
#1491=ORIENTED_EDGE('',*,*,#405,.F.);
#1492=ORIENTED_EDGE('',*,*,#1455,.F.);
#1493=ORIENTED_EDGE('',*,*,#843,.F.);
#1494=ORIENTED_EDGE('',*,*,#1471,.T.);
#1495=EDGE_LOOP('',(#1491,#1492,#1493,#1494));
#1496=FACE_BOUND('',#1495,.T.);
#1497=ADVANCED_FACE('F1053',(#1496),#1483,.T.);
#1498=CARTESIAN_POINT('',(-36.710781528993,-11.9280559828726,11.55));
#1499=DIRECTION('',(0.,0.,1.));
#1500=DIRECTION('',(-0.309016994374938,0.951056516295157,0.));
#1501=AXIS2_PLACEMENT_3D('',#1498,#1499,#1500);
#1502=PLANE('',#1501);
#1503=ORIENTED_EDGE('',*,*,#363,.F.);
#1504=CARTESIAN_POINT('',(-46.2213466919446,-15.018225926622,11.55));
#1505=DIRECTION('',(0.,0.,1.));
#1506=DIRECTION('',(-0.309016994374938,0.951056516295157,0.));
#1507=AXIS2_PLACEMENT_3D('',#1504,#1505,#1506);
#1508=CIRCLE('',#1507,10.);
#1509=EDGE_CURVE('E345',#353,#783,#1508,.T.);
#1510=ORIENTED_EDGE('',*,*,#1509,.T.);
#1511=ORIENTED_EDGE('',*,*,#784,.F.);
#1512=EDGE_CURVE('E342',#781,#362,#1508,.T.);
#1513=ORIENTED_EDGE('',*,*,#1512,.T.);
#1514=EDGE_LOOP('',(#1503,#1510,#1511,#1513));
#1515=FACE_BOUND('',#1514,.T.);
#1516=ADVANCED_FACE('F1064',(#1515),#1502,.T.);
#1517=CARTESIAN_POINT('',(-36.710781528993,-11.9280559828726,-11.55));
#1518=DIRECTION('',(0.,0.,-1.));
#1519=DIRECTION('',(0.309016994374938,-0.951056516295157,0.));
#1520=AXIS2_PLACEMENT_3D('',#1517,#1518,#1519);
#1521=PLANE('',#1520);
#1522=ORIENTED_EDGE('',*,*,#346,.F.);
#1523=CARTESIAN_POINT('',(-46.2213466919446,-15.018225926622,-11.55));
#1524=DIRECTION('',(0.,0.,1.));
#1525=DIRECTION('',(-0.309016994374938,0.951056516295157,0.));
#1526=AXIS2_PLACEMENT_3D('',#1523,#1524,#1525);
#1527=CIRCLE('',#1526,10.);
#1528=EDGE_CURVE('E346',#800,#343,#1527,.T.);
#1529=ORIENTED_EDGE('',*,*,#1528,.F.);
#1530=ORIENTED_EDGE('',*,*,#801,.F.);
#1531=EDGE_CURVE('E348',#345,#791,#1527,.T.);
#1532=ORIENTED_EDGE('',*,*,#1531,.F.);
#1533=EDGE_LOOP('',(#1522,#1529,#1530,#1532));
#1534=FACE_BOUND('',#1533,.T.);
#1535=ADVANCED_FACE('F1074',(#1534),#1521,.T.);
#1536=CARTESIAN_POINT('',(-46.2213466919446,-15.018225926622,11.55));
#1537=DIRECTION('',(0.,0.,1.));
#1538=DIRECTION('',(-0.309016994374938,0.951056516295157,0.));
#1539=AXIS2_PLACEMENT_3D('',#1536,#1537,#1538);
#1540=CYLINDRICAL_SURFACE('',#1539,10.);
#1541=ORIENTED_EDGE('',*,*,#354,.F.);
#1542=ORIENTED_EDGE('',*,*,#1531,.T.);
#1543=ORIENTED_EDGE('',*,*,#792,.F.);
#1544=ORIENTED_EDGE('',*,*,#1509,.F.);
#1545=EDGE_LOOP('',(#1541,#1542,#1543,#1544));
#1546=FACE_BOUND('',#1545,.T.);
#1547=ADVANCED_FACE('F1084',(#1546),#1540,.T.);
#1548=ORIENTED_EDGE('',*,*,#369,.F.);
#1549=ORIENTED_EDGE('',*,*,#1512,.F.);
#1550=ORIENTED_EDGE('',*,*,#807,.F.);
#1551=ORIENTED_EDGE('',*,*,#1528,.T.);
#1552=EDGE_LOOP('',(#1548,#1549,#1550,#1551));
#1553=FACE_BOUND('',#1552,.T.);
#1554=ADVANCED_FACE('F1095',(#1553),#1540,.T.);
#1555=CARTESIAN_POINT('',(-36.7107815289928,11.9280559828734,11.55));
#1556=DIRECTION('',(0.,0.,1.));
#1557=DIRECTION('',(0.309016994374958,0.95105651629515,0.));
#1558=AXIS2_PLACEMENT_3D('',#1555,#1556,#1557);
#1559=PLANE('',#1558);
#1560=ORIENTED_EDGE('',*,*,#327,.F.);
#1561=CARTESIAN_POINT('',(-46.2213466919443,15.018225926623,11.55));
#1562=DIRECTION('',(0.,0.,1.));
#1563=DIRECTION('',(0.309016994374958,0.95105651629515,0.));
#1564=AXIS2_PLACEMENT_3D('',#1561,#1562,#1563);
#1565=CIRCLE('',#1564,10.);
#1566=EDGE_CURVE('E326',#317,#747,#1565,.T.);
#1567=ORIENTED_EDGE('',*,*,#1566,.T.);
#1568=ORIENTED_EDGE('',*,*,#748,.F.);
#1569=EDGE_CURVE('E320',#745,#326,#1565,.T.);
#1570=ORIENTED_EDGE('',*,*,#1569,.T.);
#1571=EDGE_LOOP('',(#1560,#1567,#1568,#1570));
#1572=FACE_BOUND('',#1571,.T.);
#1573=ADVANCED_FACE('F1106',(#1572),#1559,.T.);
#1574=CARTESIAN_POINT('',(-36.7107815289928,11.9280559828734,-11.55));
#1575=DIRECTION('',(0.,0.,-1.));
#1576=DIRECTION('',(-0.309016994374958,-0.95105651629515,0.));
#1577=AXIS2_PLACEMENT_3D('',#1574,#1575,#1576);
#1578=PLANE('',#1577);
#1579=ORIENTED_EDGE('',*,*,#310,.F.);
#1580=CARTESIAN_POINT('',(-46.2213466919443,15.018225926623,-11.55));
#1581=DIRECTION('',(0.,0.,1.));
#1582=DIRECTION('',(0.309016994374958,0.95105651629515,0.));
#1583=AXIS2_PLACEMENT_3D('',#1580,#1581,#1582);
#1584=CIRCLE('',#1583,10.);
#1585=EDGE_CURVE('E327',#764,#307,#1584,.T.);
#1586=ORIENTED_EDGE('',*,*,#1585,.F.);
#1587=ORIENTED_EDGE('',*,*,#765,.F.);
#1588=EDGE_CURVE('E329',#309,#755,#1584,.T.);
#1589=ORIENTED_EDGE('',*,*,#1588,.F.);
#1590=EDGE_LOOP('',(#1579,#1586,#1587,#1589));
#1591=FACE_BOUND('',#1590,.T.);
#1592=ADVANCED_FACE('F1116',(#1591),#1578,.T.);
#1593=CARTESIAN_POINT('',(-46.2213466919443,15.018225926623,11.55));
#1594=DIRECTION('',(0.,0.,1.));
#1595=DIRECTION('',(0.309016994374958,0.95105651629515,0.));
#1596=AXIS2_PLACEMENT_3D('',#1593,#1594,#1595);
#1597=CYLINDRICAL_SURFACE('',#1596,10.);
#1598=ORIENTED_EDGE('',*,*,#318,.F.);
#1599=ORIENTED_EDGE('',*,*,#1588,.T.);
#1600=ORIENTED_EDGE('',*,*,#756,.F.);
#1601=ORIENTED_EDGE('',*,*,#1566,.F.);
#1602=EDGE_LOOP('',(#1598,#1599,#1600,#1601));
#1603=FACE_BOUND('',#1602,.T.);
#1604=ADVANCED_FACE('F677',(#1603),#1597,.T.);
#1605=ORIENTED_EDGE('',*,*,#333,.F.);
#1606=ORIENTED_EDGE('',*,*,#1569,.F.);
#1607=ORIENTED_EDGE('',*,*,#771,.F.);
#1608=ORIENTED_EDGE('',*,*,#1585,.T.);
#1609=EDGE_LOOP('',(#1605,#1606,#1607,#1608));
#1610=FACE_BOUND('',#1609,.T.);
#1611=ADVANCED_FACE('F668',(#1610),#1597,.T.);
#1612=CARTESIAN_POINT('',(-22.6885107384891,31.2280559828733,11.55));
#1613=DIRECTION('',(0.,0.,1.));
#1614=DIRECTION('',(0.809016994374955,0.587785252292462,0.));
#1615=AXIS2_PLACEMENT_3D('',#1612,#1613,#1614);
#1616=PLANE('',#1615);
#1617=ORIENTED_EDGE('',*,*,#291,.F.);
#1618=CARTESIAN_POINT('',(-28.5663632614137,39.3182259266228,11.55));
#1619=DIRECTION('',(0.,0.,1.));
#1620=DIRECTION('',(0.809016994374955,0.587785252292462,0.));
#1621=AXIS2_PLACEMENT_3D('',#1618,#1619,#1620);
#1622=CIRCLE('',#1621,10.);
#1623=EDGE_CURVE('E303',#281,#711,#1622,.T.);
#1624=ORIENTED_EDGE('',*,*,#1623,.T.);
#1625=ORIENTED_EDGE('',*,*,#712,.F.);
#1626=EDGE_CURVE('E61',#709,#290,#1622,.T.);
#1627=ORIENTED_EDGE('',*,*,#1626,.T.);
#1628=EDGE_LOOP('',(#1617,#1624,#1625,#1627));
#1629=FACE_BOUND('',#1628,.T.);
#1630=ADVANCED_FACE('F665',(#1629),#1616,.T.);
#1631=CARTESIAN_POINT('',(-22.6885107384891,31.2280559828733,-11.55));
#1632=DIRECTION('',(0.,0.,-1.));
#1633=DIRECTION('',(-0.809016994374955,-0.587785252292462,0.));
#1634=AXIS2_PLACEMENT_3D('',#1631,#1632,#1633);
#1635=PLANE('',#1634);
#1636=ORIENTED_EDGE('',*,*,#274,.F.);
#1637=CARTESIAN_POINT('',(-28.5663632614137,39.3182259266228,-11.55));
#1638=DIRECTION('',(0.,0.,1.));
#1639=DIRECTION('',(0.809016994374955,0.587785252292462,0.));
#1640=AXIS2_PLACEMENT_3D('',#1637,#1638,#1639);
#1641=CIRCLE('',#1640,10.);
#1642=EDGE_CURVE('E56',#728,#271,#1641,.T.);
#1643=ORIENTED_EDGE('',*,*,#1642,.F.);
#1644=ORIENTED_EDGE('',*,*,#729,.F.);
#1645=EDGE_CURVE('E301',#273,#719,#1641,.T.);
#1646=ORIENTED_EDGE('',*,*,#1645,.F.);
#1647=EDGE_LOOP('',(#1636,#1643,#1644,#1646));
#1648=FACE_BOUND('',#1647,.T.);
#1649=ADVANCED_FACE('F311',(#1648),#1635,.T.);
#1650=CARTESIAN_POINT('',(-28.5663632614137,39.3182259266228,11.55));
#1651=DIRECTION('',(0.,0.,1.));
#1652=DIRECTION('',(0.809016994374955,0.587785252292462,0.));
#1653=AXIS2_PLACEMENT_3D('',#1650,#1651,#1652);
#1654=CYLINDRICAL_SURFACE('',#1653,10.);
#1655=ORIENTED_EDGE('',*,*,#282,.F.);
#1656=ORIENTED_EDGE('',*,*,#1645,.T.);
#1657=ORIENTED_EDGE('',*,*,#720,.F.);
#1658=ORIENTED_EDGE('',*,*,#1623,.F.);
#1659=EDGE_LOOP('',(#1655,#1656,#1657,#1658));
#1660=FACE_BOUND('',#1659,.T.);
#1661=ADVANCED_FACE('F300',(#1660),#1654,.T.);
#1662=ORIENTED_EDGE('',*,*,#297,.F.);
#1663=ORIENTED_EDGE('',*,*,#1626,.F.);
#1664=ORIENTED_EDGE('',*,*,#735,.F.);
#1665=ORIENTED_EDGE('',*,*,#1642,.T.);
#1666=EDGE_LOOP('',(#1662,#1663,#1664,#1665));
#1667=FACE_BOUND('',#1666,.T.);
#1668=ADVANCED_FACE('F1163',(#1667),#1654,.T.);
#1669=CLOSED_SHELL('',(#46,#74,#113,#152,#174,#191,#219,#239,#259,#609,#629,#649,#669,#697,
#1055,#1083,#1095,#1107,#1119,#1131,#1143,#1155,#1174,#1193,#1205,#1212,#1231,#1250,#1262,#1269,
#1288,#1307,#1319,#1326,#1345,#1364,#1376,#1383,#1402,#1421,#1433,#1440,#1459,#1478,#1490,#1497,
#1516,#1535,#1547,#1554,#1573,#1592,#1604,#1611,#1630,#1649,#1661,#1668));
#1670=MANIFOLD_SOLID_BREP('B2',#1669);
#1671=ADVANCED_BREP_SHAPE_REPRESENTATION('',(#18,#1670),#14);
#1672=SHAPE_DEFINITION_REPRESENTATION(#9,#1671);
ENDSEC;
END-ISO-10303-21;
